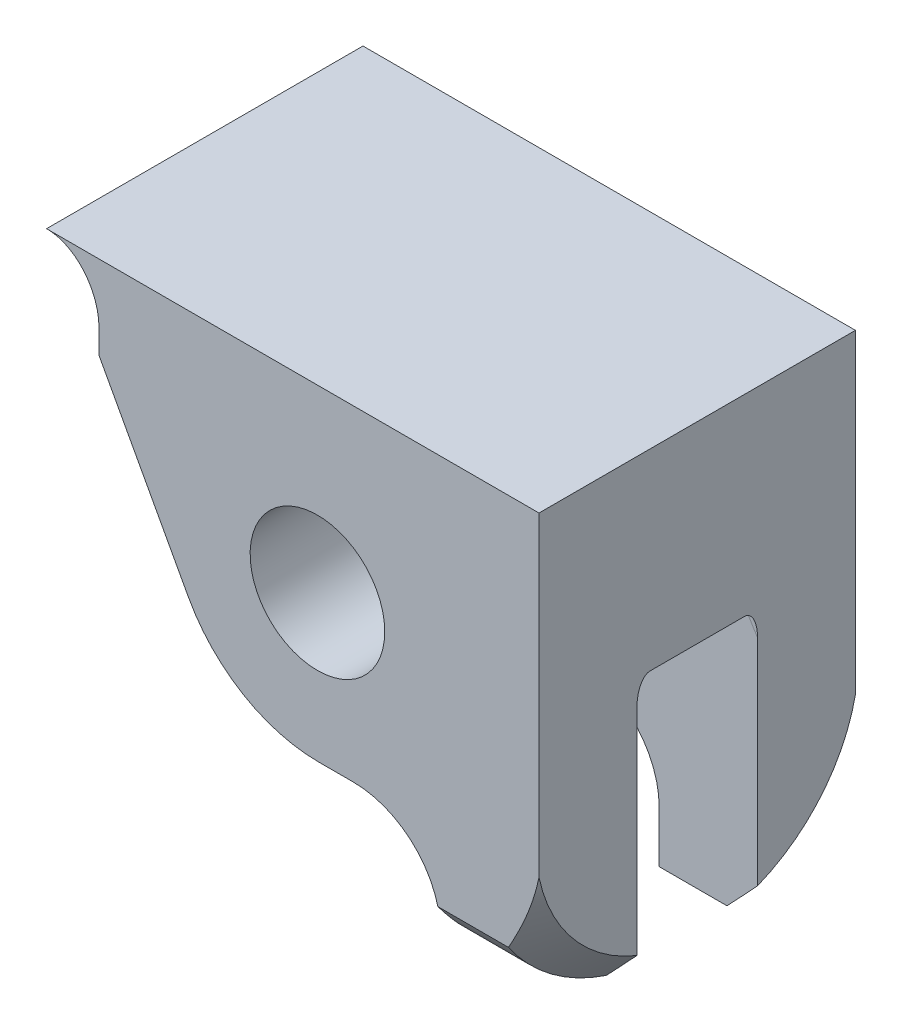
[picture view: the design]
ISO-10303-21;
HEADER;
FILE_DESCRIPTION(('STEP AP214'),'2;1');
FILE_NAME('part.step','',(''),(''),'','','');
FILE_SCHEMA(('AUTOMOTIVE_DESIGN { 1 0 10303 214 1 1 1 1 }'));
ENDSEC;
DATA;
#1=APPLICATION_CONTEXT('core data for automotive mechanical design processes');
#2=APPLICATION_PROTOCOL_DEFINITION('international standard','automotive_design',2000,#1);
#3=PRODUCT_CONTEXT('',#1,'mechanical');
#4=PRODUCT('Part','Part','',(#3));
#5=PRODUCT_RELATED_PRODUCT_CATEGORY('part','',(#4));
#6=PRODUCT_DEFINITION_FORMATION('','',#4);
#7=PRODUCT_DEFINITION_CONTEXT('part definition',#1,'design');
#8=PRODUCT_DEFINITION('design','',#6,#7);
#9=PRODUCT_DEFINITION_SHAPE('','',#8);
#10=(LENGTH_UNIT() NAMED_UNIT(*) SI_UNIT(.MILLI.,.METRE.));
#11=(NAMED_UNIT(*) PLANE_ANGLE_UNIT() SI_UNIT($,.RADIAN.));
#12=(NAMED_UNIT(*) SI_UNIT($,.STERADIAN.) SOLID_ANGLE_UNIT());
#13=UNCERTAINTY_MEASURE_WITH_UNIT(LENGTH_MEASURE(1.E-05),#10,'distance_accuracy_value','');
#14=(GEOMETRIC_REPRESENTATION_CONTEXT(3) GLOBAL_UNCERTAINTY_ASSIGNED_CONTEXT((#13)) GLOBAL_UNIT_ASSIGNED_CONTEXT((#10,
#11,#12)) REPRESENTATION_CONTEXT('',''));
#15=CARTESIAN_POINT('',(0.,0.,0.));
#16=DIRECTION('',(0.,0.,1.));
#17=DIRECTION('',(1.,0.,0.));
#18=AXIS2_PLACEMENT_3D('',#15,#16,#17);
#19=CARTESIAN_POINT('',(-20.8250166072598,0.,0.));
#20=DIRECTION('',(1.,0.,0.));
#21=DIRECTION('',(0.,0.,-1.));
#22=AXIS2_PLACEMENT_3D('',#19,#20,#21);
#23=PLANE('',#22);
#24=DIRECTION('',(0.,0.,-1.));
#25=VECTOR('',#24,1.);
#26=CARTESIAN_POINT('',(-20.8250166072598,-7.54952779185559,0.));
#27=LINE('',#26,#25);
#28=CARTESIAN_POINT('',(-20.8250166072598,-7.54952779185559,4.5974));
#29=VERTEX_POINT('',#28);
#30=CARTESIAN_POINT('',(-20.8250166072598,-7.54952779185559,-4.5974));
#31=VERTEX_POINT('',#30);
#32=EDGE_CURVE('E35',#29,#31,#27,.T.);
#33=ORIENTED_EDGE('',*,*,#32,.T.);
#34=CARTESIAN_POINT('',(-20.8250166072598,0.,0.));
#35=DIRECTION('',(-1.,0.,0.));
#36=DIRECTION('',(0.,0.,1.));
#37=AXIS2_PLACEMENT_3D('',#34,#35,#36);
#38=CIRCLE('',#37,8.83919999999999);
#39=EDGE_CURVE('E46',#31,#29,#38,.T.);
#40=ORIENTED_EDGE('',*,*,#39,.T.);
#41=EDGE_LOOP('',(#33,#40));
#42=FACE_BOUND('',#41,.T.);
#43=ADVANCED_FACE('F32',(#42),#23,.F.);
#44=CARTESIAN_POINT('',(0.,-7.54952779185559,0.));
#45=DIRECTION('',(0.,1.,0.));
#46=DIRECTION('',(0.,0.,1.));
#47=AXIS2_PLACEMENT_3D('',#44,#45,#46);
#48=PLANE('',#47);
#49=DIRECTION('',(1.,0.,0.));
#50=VECTOR('',#49,1.);
#51=CARTESIAN_POINT('',(-47.752,-7.54952779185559,4.5974));
#52=LINE('',#51,#50);
#53=CARTESIAN_POINT('',(-6.5151,-7.54952779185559,4.5974));
#54=VERTEX_POINT('',#53);
#55=EDGE_CURVE('E274',#29,#54,#52,.T.);
#56=ORIENTED_EDGE('',*,*,#55,.T.);
#57=DIRECTION('',(0.,0.,-1.));
#58=VECTOR('',#57,1.);
#59=CARTESIAN_POINT('',(-6.51509999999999,-7.54952779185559,0.));
#60=LINE('',#59,#58);
#61=CARTESIAN_POINT('',(-6.5151,-7.54952779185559,-4.59740000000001));
#62=VERTEX_POINT('',#61);
#63=EDGE_CURVE('E11',#54,#62,#60,.T.);
#64=ORIENTED_EDGE('',*,*,#63,.T.);
#65=DIRECTION('',(1.,0.,0.));
#66=VECTOR('',#65,1.);
#67=CARTESIAN_POINT('',(-47.752,-7.54952779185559,-4.5974));
#68=LINE('',#67,#66);
#69=EDGE_CURVE('E273',#31,#62,#68,.T.);
#70=ORIENTED_EDGE('',*,*,#69,.F.);
#71=ORIENTED_EDGE('',*,*,#32,.F.);
#72=EDGE_LOOP('',(#56,#64,#70,#71));
#73=FACE_BOUND('',#72,.T.);
#74=ADVANCED_FACE('F348',(#73),#48,.T.);
#75=CARTESIAN_POINT('',(-19.3010166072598,-10.3632,0.));
#76=DIRECTION('',(1.,0.,0.));
#77=DIRECTION('',(0.,0.,-1.));
#78=AXIS2_PLACEMENT_3D('',#75,#76,#77);
#79=PLANE('',#78);
#80=DIRECTION('',(0.,1.,0.));
#81=VECTOR('',#80,1.);
#82=CARTESIAN_POINT('',(-19.3010166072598,-7.54952779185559,4.5974));
#83=LINE('',#82,#81);
#84=CARTESIAN_POINT('',(-19.3010166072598,-9.9761533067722,4.5974));
#85=VERTEX_POINT('',#84);
#86=CARTESIAN_POINT('',(-19.3010166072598,-9.28761688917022,4.5974));
#87=VERTEX_POINT('',#86);
#88=EDGE_CURVE('E299',#85,#87,#83,.T.);
#89=ORIENTED_EDGE('',*,*,#88,.T.);
#90=CARTESIAN_POINT('',(-19.3010166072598,0.,0.));
#91=DIRECTION('',(-1.,0.,0.));
#92=DIRECTION('',(0.,0.,1.));
#93=AXIS2_PLACEMENT_3D('',#90,#91,#92);
#94=CIRCLE('',#93,10.3632);
#95=CARTESIAN_POINT('',(-19.3010166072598,-9.97615330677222,2.80575826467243));
#96=VERTEX_POINT('',#95);
#97=EDGE_CURVE('E507',#96,#87,#94,.T.);
#98=ORIENTED_EDGE('',*,*,#97,.F.);
#99=DIRECTION('',(0.,0.,-1.));
#100=VECTOR('',#99,1.);
#101=CARTESIAN_POINT('',(-19.3010166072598,-9.9761533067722,-5.14985));
#102=LINE('',#101,#100);
#103=EDGE_CURVE('E302',#85,#96,#102,.T.);
#104=ORIENTED_EDGE('',*,*,#103,.F.);
#105=EDGE_LOOP('',(#89,#98,#104));
#106=FACE_BOUND('',#105,.T.);
#107=ADVANCED_FACE('F351',(#106),#79,.F.);
#108=DIRECTION('',(0.,-1.,0.));
#109=VECTOR('',#108,1.);
#110=CARTESIAN_POINT('',(-19.3010166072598,-18.9244220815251,-4.5974));
#111=LINE('',#110,#109);
#112=CARTESIAN_POINT('',(-19.3010166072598,-9.28761688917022,-4.5974));
#113=VERTEX_POINT('',#112);
#114=CARTESIAN_POINT('',(-19.3010166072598,-9.9761533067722,-4.5974));
#115=VERTEX_POINT('',#114);
#116=EDGE_CURVE('E437',#113,#115,#111,.T.);
#117=ORIENTED_EDGE('',*,*,#116,.T.);
#118=CARTESIAN_POINT('',(-19.3010166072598,-9.97615330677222,-2.80575826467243));
#119=VERTEX_POINT('',#118);
#120=EDGE_CURVE('E296',#119,#115,#102,.T.);
#121=ORIENTED_EDGE('',*,*,#120,.F.);
#122=EDGE_CURVE('E509',#113,#119,#94,.T.);
#123=ORIENTED_EDGE('',*,*,#122,.F.);
#124=EDGE_LOOP('',(#117,#121,#123));
#125=FACE_BOUND('',#124,.T.);
#126=ADVANCED_FACE('F358',(#125),#79,.F.);
#127=CARTESIAN_POINT('',(-12.954,-12.7762,-5.14985));
#128=DIRECTION('',(0.,0.,1.));
#129=DIRECTION('',(1.,0.,0.));
#130=AXIS2_PLACEMENT_3D('',#127,#128,#129);
#131=CYLINDRICAL_SURFACE('',#130,1.9558);
#132=CARTESIAN_POINT('',(-12.954,-12.7762,-4.5974));
#133=DIRECTION('',(0.,0.,-1.));
#134=DIRECTION('',(0.,1.,0.));
#135=AXIS2_PLACEMENT_3D('',#132,#133,#134);
#136=CIRCLE('',#135,1.9558);
#137=CARTESIAN_POINT('',(-12.954,-10.8204,-4.5974));
#138=VERTEX_POINT('',#137);
#139=EDGE_CURVE('E222',#138,#138,#136,.T.);
#140=ORIENTED_EDGE('',*,*,#139,.T.);
#141=EDGE_LOOP('',(#140));
#142=FACE_BOUND('',#141,.T.);
#143=CARTESIAN_POINT('',(-12.954,-12.7762,-1.7526));
#144=DIRECTION('',(0.,0.,1.));
#145=DIRECTION('',(1.,0.,0.));
#146=AXIS2_PLACEMENT_3D('',#143,#144,#145);
#147=CIRCLE('',#146,1.9558);
#148=CARTESIAN_POINT('',(-10.9982,-12.7762,-1.7526));
#149=VERTEX_POINT('',#148);
#150=EDGE_CURVE('E501',#149,#149,#147,.F.);
#151=ORIENTED_EDGE('',*,*,#150,.F.);
#152=EDGE_LOOP('',(#151));
#153=FACE_BOUND('',#152,.T.);
#154=ADVANCED_FACE('F525',(#142,#153),#131,.F.);
#155=CARTESIAN_POINT('',(-9.3726,-19.558,-5.14985));
#156=DIRECTION('',(1.,0.,0.));
#157=DIRECTION('',(0.,1.,0.));
#158=AXIS2_PLACEMENT_3D('',#155,#156,#157);
#159=PLANE('',#158);
#160=DIRECTION('',(0.,-1.,0.));
#161=VECTOR('',#160,1.);
#162=CARTESIAN_POINT('',(-9.3726,-19.558,-1.7526));
#163=LINE('',#162,#161);
#164=CARTESIAN_POINT('',(-9.3726,-19.558,-1.7526));
#165=VERTEX_POINT('',#164);
#166=CARTESIAN_POINT('',(-9.3726,-21.0540472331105,-1.7526));
#167=VERTEX_POINT('',#166);
#168=EDGE_CURVE('E493',#165,#167,#163,.T.);
#169=ORIENTED_EDGE('',*,*,#168,.F.);
#170=DIRECTION('',(0.,0.,1.));
#171=VECTOR('',#170,1.);
#172=CARTESIAN_POINT('',(-9.3726,-19.558,-5.14985));
#173=LINE('',#172,#171);
#174=CARTESIAN_POINT('',(-9.3726,-19.558,-4.08774314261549));
#175=VERTEX_POINT('',#174);
#176=EDGE_CURVE('E226',#175,#165,#173,.T.);
#177=ORIENTED_EDGE('',*,*,#176,.F.);
#178=CARTESIAN_POINT('',(-9.37260000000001,-15.748,0.));
#179=DIRECTION('',(1.,0.,0.));
#180=DIRECTION('',(0.,1.,0.));
#181=AXIS2_PLACEMENT_3D('',#178,#179,#180);
#182=CIRCLE('',#181,5.588);
#183=EDGE_CURVE('E293',#175,#167,#182,.F.);
#184=ORIENTED_EDGE('',*,*,#183,.T.);
#185=EDGE_LOOP('',(#169,#177,#184));
#186=FACE_BOUND('',#185,.T.);
#187=ADVANCED_FACE('F561',(#186),#159,.F.);
#188=CARTESIAN_POINT('',(-11.9126,-19.558,-5.14985));
#189=DIRECTION('',(0.,0.,1.));
#190=DIRECTION('',(1.,0.,0.));
#191=AXIS2_PLACEMENT_3D('',#188,#189,#190);
#192=CYLINDRICAL_SURFACE('',#191,2.54);
#193=CARTESIAN_POINT('',(-11.9126,-19.558,-1.7526));
#194=DIRECTION('',(0.,0.,1.));
#195=DIRECTION('',(1.,0.,0.));
#196=AXIS2_PLACEMENT_3D('',#193,#194,#195);
#197=CIRCLE('',#196,2.54);
#198=CARTESIAN_POINT('',(-11.9126,-17.018,-1.7526));
#199=VERTEX_POINT('',#198);
#200=EDGE_CURVE('E491',#199,#165,#197,.F.);
#201=ORIENTED_EDGE('',*,*,#200,.F.);
#202=DIRECTION('',(0.,0.,1.));
#203=VECTOR('',#202,1.);
#204=CARTESIAN_POINT('',(-11.9126,-17.018,-5.14985));
#205=LINE('',#204,#203);
#206=CARTESIAN_POINT('',(-11.9126,-17.018,-4.5974));
#207=VERTEX_POINT('',#206);
#208=EDGE_CURVE('E442',#207,#199,#205,.T.);
#209=ORIENTED_EDGE('',*,*,#208,.F.);
#210=CARTESIAN_POINT('',(-11.9126,-19.558,-4.5974));
#211=DIRECTION('',(0.,0.,-1.));
#212=DIRECTION('',(0.,1.,0.));
#213=AXIS2_PLACEMENT_3D('',#210,#211,#212);
#214=CIRCLE('',#213,2.54);
#215=CARTESIAN_POINT('',(-9.4528888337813,-18.9244220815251,-4.5974));
#216=VERTEX_POINT('',#215);
#217=EDGE_CURVE('E290',#207,#216,#214,.T.);
#218=ORIENTED_EDGE('',*,*,#217,.T.);
#219=CARTESIAN_POINT('',(-9.97381391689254,-17.9170525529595,-5.14985));
#220=CARTESIAN_POINT('',(-9.92846202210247,-17.9706111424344,-5.12730256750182));
#221=CARTESIAN_POINT('',(-9.88570291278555,-18.0256568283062,-5.10312410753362));
#222=CARTESIAN_POINT('',(-9.80549953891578,-18.1379772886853,-5.05148902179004));
#223=CARTESIAN_POINT('',(-9.76805189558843,-18.1952506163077,-5.02403450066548));
#224=CARTESIAN_POINT('',(-9.6987847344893,-18.3109469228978,-4.9660053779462));
#225=CARTESIAN_POINT('',(-9.66692780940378,-18.3693591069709,-4.93545385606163));
#226=CARTESIAN_POINT('',(-9.60848600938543,-18.4870290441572,-4.8711365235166));
#227=CARTESIAN_POINT('',(-9.5819015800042,-18.546286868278,-4.83737044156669));
#228=CARTESIAN_POINT('',(-9.50999982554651,-18.724094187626,-4.73154460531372));
#229=CARTESIAN_POINT('',(-9.47233207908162,-18.8430243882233,-4.65478617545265));
#230=CARTESIAN_POINT('',(-9.4155283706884,-19.0775349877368,-4.49004914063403));
#231=CARTESIAN_POINT('',(-9.3964151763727,-19.1931111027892,-4.40205690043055));
#232=CARTESIAN_POINT('',(-9.38087414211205,-19.3485949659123,-4.27371216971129));
#233=CARTESIAN_POINT('',(-9.37772427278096,-19.3912949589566,-4.2373694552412));
#234=CARTESIAN_POINT('',(-9.37359111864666,-19.4755163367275,-4.1634707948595));
#235=CARTESIAN_POINT('',(-9.37260143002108,-19.5170408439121,-4.1259187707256));
#236=CARTESIAN_POINT('',(-9.3726,-19.558,-4.08774314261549));
#237=B_SPLINE_CURVE_WITH_KNOTS('',3,(#219,#220,#221,#222,#223,#224,#225,#226,#227,#228,#229,
#230,#231,#232,#233,#234,#235,#236),.UNSPECIFIED.,.F.,.F.,(4,2,2,2,2,2,2,2,4),(0.,
0.221040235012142,0.441939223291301,0.661298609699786,0.880676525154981,1.31813990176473,
1.75613939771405,1.92457157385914,2.0925037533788),.UNSPECIFIED.);
#238=EDGE_CURVE('E230',#216,#175,#237,.T.);
#239=ORIENTED_EDGE('',*,*,#238,.T.);
#240=ORIENTED_EDGE('',*,*,#176,.T.);
#241=EDGE_LOOP('',(#201,#209,#218,#239,#240));
#242=FACE_BOUND('',#241,.T.);
#243=ADVANCED_FACE('F253',(#242),#192,.F.);
#244=CARTESIAN_POINT('',(-12.9086657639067,-17.018,-5.14985));
#245=DIRECTION('',(0.,1.,0.));
#246=DIRECTION('',(-1.,0.,0.));
#247=AXIS2_PLACEMENT_3D('',#244,#245,#246);
#248=PLANE('',#247);
#249=DIRECTION('',(1.,0.,0.));
#250=VECTOR('',#249,1.);
#251=CARTESIAN_POINT('',(-12.9086657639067,-17.018,-1.7526));
#252=LINE('',#251,#250);
#253=CARTESIAN_POINT('',(-12.9086657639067,-17.018,-1.7526));
#254=VERTEX_POINT('',#253);
#255=EDGE_CURVE('E489',#254,#199,#252,.T.);
#256=ORIENTED_EDGE('',*,*,#255,.F.);
#257=DIRECTION('',(0.,0.,1.));
#258=VECTOR('',#257,1.);
#259=CARTESIAN_POINT('',(-12.9086657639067,-17.018,-5.14985));
#260=LINE('',#259,#258);
#261=CARTESIAN_POINT('',(-12.9086657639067,-17.018,-4.5974));
#262=VERTEX_POINT('',#261);
#263=EDGE_CURVE('E231',#262,#254,#260,.T.);
#264=ORIENTED_EDGE('',*,*,#263,.F.);
#265=DIRECTION('',(1.,0.,0.));
#266=VECTOR('',#265,1.);
#267=CARTESIAN_POINT('',(-47.752,-17.0180000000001,-4.5974));
#268=LINE('',#267,#266);
#269=EDGE_CURVE('E288',#262,#207,#268,.T.);
#270=ORIENTED_EDGE('',*,*,#269,.T.);
#271=ORIENTED_EDGE('',*,*,#208,.T.);
#272=EDGE_LOOP('',(#256,#264,#270,#271));
#273=FACE_BOUND('',#272,.T.);
#274=ADVANCED_FACE('F531',(#273),#248,.F.);
#275=CARTESIAN_POINT('',(-12.9086657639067,-12.7,-5.14985));
#276=DIRECTION('',(0.,0.,1.));
#277=DIRECTION('',(1.,0.,0.));
#278=AXIS2_PLACEMENT_3D('',#275,#276,#277);
#279=CYLINDRICAL_SURFACE('',#278,4.318);
#280=CARTESIAN_POINT('',(-12.9086657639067,-12.7,-1.7526));
#281=DIRECTION('',(0.,0.,1.));
#282=DIRECTION('',(1.,0.,0.));
#283=AXIS2_PLACEMENT_3D('',#280,#281,#282);
#284=CIRCLE('',#283,4.318);
#285=CARTESIAN_POINT('',(-16.7033980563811,-14.760371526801,-1.7526));
#286=VERTEX_POINT('',#285);
#287=EDGE_CURVE('E487',#286,#254,#284,.T.);
#288=ORIENTED_EDGE('',*,*,#287,.F.);
#289=DIRECTION('',(0.,0.,1.));
#290=VECTOR('',#289,1.);
#291=CARTESIAN_POINT('',(-16.7033980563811,-14.760371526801,-5.14985));
#292=LINE('',#291,#290);
#293=CARTESIAN_POINT('',(-16.7033980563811,-14.760371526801,-4.5974));
#294=VERTEX_POINT('',#293);
#295=EDGE_CURVE('E216',#294,#286,#292,.T.);
#296=ORIENTED_EDGE('',*,*,#295,.F.);
#297=CARTESIAN_POINT('',(-12.9086657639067,-12.7,-4.5974));
#298=DIRECTION('',(0.,0.,-1.));
#299=DIRECTION('',(0.,1.,0.));
#300=AXIS2_PLACEMENT_3D('',#297,#298,#299);
#301=CIRCLE('',#300,4.318);
#302=EDGE_CURVE('E286',#294,#262,#301,.F.);
#303=ORIENTED_EDGE('',*,*,#302,.T.);
#304=ORIENTED_EDGE('',*,*,#263,.T.);
#305=EDGE_LOOP('',(#288,#296,#303,#304));
#306=FACE_BOUND('',#305,.T.);
#307=ADVANCED_FACE('F523',(#306),#279,.T.);
#308=CARTESIAN_POINT('',(-19.9183318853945,-8.8392,-5.14985));
#309=DIRECTION('',(0.878817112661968,0.477158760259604,0.));
#310=DIRECTION('',(-0.477158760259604,0.878817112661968,0.));
#311=AXIS2_PLACEMENT_3D('',#308,#309,#310);
#312=PLANE('',#311);
#313=DIRECTION('',(0.477158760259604,-0.878817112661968,0.));
#314=VECTOR('',#313,1.);
#315=CARTESIAN_POINT('',(-19.9183318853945,-8.8392,-1.7526));
#316=LINE('',#315,#314);
#317=CARTESIAN_POINT('',(-19.3273360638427,-9.92767889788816,-1.7526));
#318=VERTEX_POINT('',#317);
#319=EDGE_CURVE('E485',#318,#286,#316,.T.);
#320=ORIENTED_EDGE('',*,*,#319,.F.);
#321=CARTESIAN_POINT('',(-19.4856993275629,-9.63601004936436,0.));
#322=CARTESIAN_POINT('',(-19.4845018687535,-9.63821549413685,-0.00913515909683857));
#323=CARTESIAN_POINT('',(-19.4833098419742,-9.64041093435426,-0.0182737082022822));
#324=CARTESIAN_POINT('',(-19.4177100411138,-9.76123073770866,-0.523680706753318));
#325=CARTESIAN_POINT('',(-19.3693390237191,-9.85031906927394,-1.02984150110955));
#326=CARTESIAN_POINT('',(-19.3084355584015,-9.96248929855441,-2.05247010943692));
#327=CARTESIAN_POINT('',(-19.2959541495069,-9.98547719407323,-2.56895155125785));
#328=CARTESIAN_POINT('',(-19.3063645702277,-9.9663035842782,-3.34237693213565));
#329=CARTESIAN_POINT('',(-19.3147285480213,-9.95089905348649,-3.60039859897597));
#330=CARTESIAN_POINT('',(-19.3415154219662,-9.90156376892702,-4.11416173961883));
#331=CARTESIAN_POINT('',(-19.3599368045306,-9.86763580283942,-4.36990355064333));
#332=CARTESIAN_POINT('',(-19.4071596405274,-9.78066215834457,-4.87789800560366));
#333=CARTESIAN_POINT('',(-19.4359894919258,-9.72756417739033,-5.13013912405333));
#334=CARTESIAN_POINT('',(-19.5042264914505,-9.60188725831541,-5.62844766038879));
#335=CARTESIAN_POINT('',(-19.5436415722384,-9.52929371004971,-5.87451029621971));
#336=CARTESIAN_POINT('',(-19.5884304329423,-9.44680289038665,-6.11630962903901));
#337=B_SPLINE_CURVE_WITH_KNOTS('',3,(#321,#322,#323,#324,#325,#326,#327,#328,#329,#330,#331,
#332,#333,#334,#335,#336),.UNSPECIFIED.,.F.,.F.,(4,2,2,2,2,2,2,4),(0.,0.0284215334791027,
1.57127409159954,3.11631967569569,3.89143286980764,4.66642944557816,5.44355666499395,
6.22126790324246),.UNSPECIFIED.);
#338=EDGE_CURVE('E429',#318,#119,#337,.T.);
#339=ORIENTED_EDGE('',*,*,#338,.T.);
#340=ORIENTED_EDGE('',*,*,#120,.T.);
#341=DIRECTION('',(0.477158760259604,-0.878817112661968,0.));
#342=VECTOR('',#341,1.);
#343=CARTESIAN_POINT('',(-22.0264254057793,-4.95657472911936,-4.59740000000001));
#344=LINE('',#343,#342);
#345=EDGE_CURVE('E284',#115,#294,#344,.T.);
#346=ORIENTED_EDGE('',*,*,#345,.T.);
#347=ORIENTED_EDGE('',*,*,#295,.T.);
#348=EDGE_LOOP('',(#320,#339,#340,#346,#347));
#349=FACE_BOUND('',#348,.T.);
#350=ADVANCED_FACE('F517',(#349),#312,.F.);
#351=CARTESIAN_POINT('',(-12.954,-12.7762,1.7526));
#352=DIRECTION('',(0.,0.,1.));
#353=DIRECTION('',(1.,0.,0.));
#354=AXIS2_PLACEMENT_3D('',#351,#352,#353);
#355=CIRCLE('',#354,1.9558);
#356=CARTESIAN_POINT('',(-10.9982,-12.7762,1.7526));
#357=VERTEX_POINT('',#356);
#358=EDGE_CURVE('E482',#357,#357,#355,.F.);
#359=ORIENTED_EDGE('',*,*,#358,.T.);
#360=EDGE_LOOP('',(#359));
#361=FACE_BOUND('',#360,.T.);
#362=CARTESIAN_POINT('',(-12.954,-12.7762,4.5974));
#363=DIRECTION('',(0.,0.,1.));
#364=DIRECTION('',(0.,-1.,0.));
#365=AXIS2_PLACEMENT_3D('',#362,#363,#364);
#366=CIRCLE('',#365,1.9558);
#367=CARTESIAN_POINT('',(-12.954,-14.732,4.5974));
#368=VERTEX_POINT('',#367);
#369=EDGE_CURVE('E217',#368,#368,#366,.T.);
#370=ORIENTED_EDGE('',*,*,#369,.T.);
#371=EDGE_LOOP('',(#370));
#372=FACE_BOUND('',#371,.T.);
#373=ADVANCED_FACE('F516',(#361,#372),#131,.F.);
#374=CARTESIAN_POINT('',(-19.4856993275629,-9.63601004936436,0.));
#375=CARTESIAN_POINT('',(-19.4845018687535,-9.63821549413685,0.00913515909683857));
#376=CARTESIAN_POINT('',(-19.4833098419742,-9.64041093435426,0.0182737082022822));
#377=CARTESIAN_POINT('',(-19.4177100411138,-9.76123073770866,0.523680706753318));
#378=CARTESIAN_POINT('',(-19.3693390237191,-9.85031906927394,1.02984150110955));
#379=CARTESIAN_POINT('',(-19.3084355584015,-9.96248929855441,2.05247010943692));
#380=CARTESIAN_POINT('',(-19.2959541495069,-9.98547719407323,2.56895155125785));
#381=CARTESIAN_POINT('',(-19.3063645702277,-9.9663035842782,3.34237693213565));
#382=CARTESIAN_POINT('',(-19.3147285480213,-9.95089905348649,3.60039859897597));
#383=CARTESIAN_POINT('',(-19.3415154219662,-9.90156376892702,4.11416173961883));
#384=CARTESIAN_POINT('',(-19.3599368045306,-9.86763580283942,4.36990355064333));
#385=CARTESIAN_POINT('',(-19.4071596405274,-9.78066215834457,4.87789800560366));
#386=CARTESIAN_POINT('',(-19.4359894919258,-9.72756417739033,5.13013912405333));
#387=CARTESIAN_POINT('',(-19.5042264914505,-9.60188725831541,5.62844766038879));
#388=CARTESIAN_POINT('',(-19.5436415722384,-9.52929371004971,5.87451029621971));
#389=CARTESIAN_POINT('',(-19.5884304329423,-9.44680289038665,6.11630962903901));
#390=B_SPLINE_CURVE_WITH_KNOTS('',3,(#374,#375,#376,#377,#378,#379,#380,#381,#382,#383,#384,
#385,#386,#387,#388,#389),.UNSPECIFIED.,.F.,.F.,(4,2,2,2,2,2,2,4),(0.,0.0284215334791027,
1.57127409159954,3.11631967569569,3.89143286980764,4.66642944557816,5.44355666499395,
6.22126790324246),.UNSPECIFIED.);
#391=CARTESIAN_POINT('',(-19.3273360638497,-9.92767889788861,1.7526));
#392=VERTEX_POINT('',#391);
#393=EDGE_CURVE('E210',#96,#392,#390,.F.);
#394=ORIENTED_EDGE('',*,*,#393,.T.);
#395=DIRECTION('',(0.477158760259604,-0.878817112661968,0.));
#396=VECTOR('',#395,1.);
#397=CARTESIAN_POINT('',(-19.9183318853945,-8.8392,1.7526));
#398=LINE('',#397,#396);
#399=CARTESIAN_POINT('',(-16.7033980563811,-14.760371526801,1.7526));
#400=VERTEX_POINT('',#399);
#401=EDGE_CURVE('E196',#392,#400,#398,.T.);
#402=ORIENTED_EDGE('',*,*,#401,.T.);
#403=CARTESIAN_POINT('',(-16.7033980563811,-14.760371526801,4.5974));
#404=VERTEX_POINT('',#403);
#405=EDGE_CURVE('E207',#400,#404,#292,.T.);
#406=ORIENTED_EDGE('',*,*,#405,.T.);
#407=DIRECTION('',(-0.477158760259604,0.878817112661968,0.));
#408=VECTOR('',#407,1.);
#409=CARTESIAN_POINT('',(-26.7963199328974,3.82847814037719,4.5974));
#410=LINE('',#409,#408);
#411=EDGE_CURVE('E228',#404,#85,#410,.T.);
#412=ORIENTED_EDGE('',*,*,#411,.T.);
#413=ORIENTED_EDGE('',*,*,#103,.T.);
#414=EDGE_LOOP('',(#394,#402,#406,#412,#413));
#415=FACE_BOUND('',#414,.T.);
#416=ADVANCED_FACE('F205',(#415),#312,.F.);
#417=ORIENTED_EDGE('',*,*,#405,.F.);
#418=CARTESIAN_POINT('',(-12.9086657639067,-12.7,1.7526));
#419=DIRECTION('',(0.,0.,1.));
#420=DIRECTION('',(1.,0.,0.));
#421=AXIS2_PLACEMENT_3D('',#418,#419,#420);
#422=CIRCLE('',#421,4.318);
#423=CARTESIAN_POINT('',(-12.9086657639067,-17.018,1.7526));
#424=VERTEX_POINT('',#423);
#425=EDGE_CURVE('E190',#400,#424,#422,.T.);
#426=ORIENTED_EDGE('',*,*,#425,.T.);
#427=CARTESIAN_POINT('',(-12.9086657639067,-17.018,4.5974));
#428=VERTEX_POINT('',#427);
#429=EDGE_CURVE('E441',#424,#428,#260,.T.);
#430=ORIENTED_EDGE('',*,*,#429,.T.);
#431=CARTESIAN_POINT('',(-12.9086657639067,-12.7,4.5974));
#432=DIRECTION('',(0.,0.,1.));
#433=DIRECTION('',(0.,-1.,0.));
#434=AXIS2_PLACEMENT_3D('',#431,#432,#433);
#435=CIRCLE('',#434,4.318);
#436=EDGE_CURVE('E214',#428,#404,#435,.F.);
#437=ORIENTED_EDGE('',*,*,#436,.T.);
#438=EDGE_LOOP('',(#417,#426,#430,#437));
#439=FACE_BOUND('',#438,.T.);
#440=ADVANCED_FACE('F212',(#439),#279,.T.);
#441=ORIENTED_EDGE('',*,*,#429,.F.);
#442=DIRECTION('',(1.,0.,0.));
#443=VECTOR('',#442,1.);
#444=CARTESIAN_POINT('',(-12.9086657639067,-17.018,1.7526));
#445=LINE('',#444,#443);
#446=CARTESIAN_POINT('',(-11.9126,-17.018,1.7526));
#447=VERTEX_POINT('',#446);
#448=EDGE_CURVE('E199',#424,#447,#445,.T.);
#449=ORIENTED_EDGE('',*,*,#448,.T.);
#450=CARTESIAN_POINT('',(-11.9126,-17.018,4.5974));
#451=VERTEX_POINT('',#450);
#452=EDGE_CURVE('E444',#447,#451,#205,.T.);
#453=ORIENTED_EDGE('',*,*,#452,.T.);
#454=DIRECTION('',(-1.,0.,0.));
#455=VECTOR('',#454,1.);
#456=CARTESIAN_POINT('',(-47.752,-17.0180000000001,4.5974));
#457=LINE('',#456,#455);
#458=EDGE_CURVE('E262',#451,#428,#457,.T.);
#459=ORIENTED_EDGE('',*,*,#458,.T.);
#460=EDGE_LOOP('',(#441,#449,#453,#459));
#461=FACE_BOUND('',#460,.T.);
#462=ADVANCED_FACE('F251',(#461),#248,.F.);
#463=ORIENTED_EDGE('',*,*,#452,.F.);
#464=CARTESIAN_POINT('',(-11.9126,-19.558,1.7526));
#465=DIRECTION('',(0.,0.,1.));
#466=DIRECTION('',(1.,0.,0.));
#467=AXIS2_PLACEMENT_3D('',#464,#465,#466);
#468=CIRCLE('',#467,2.54);
#469=CARTESIAN_POINT('',(-9.3726,-19.558,1.7526));
#470=VERTEX_POINT('',#469);
#471=EDGE_CURVE('E460',#447,#470,#468,.F.);
#472=ORIENTED_EDGE('',*,*,#471,.T.);
#473=CARTESIAN_POINT('',(-9.3726,-19.558,4.08774314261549));
#474=VERTEX_POINT('',#473);
#475=EDGE_CURVE('E220',#470,#474,#173,.T.);
#476=ORIENTED_EDGE('',*,*,#475,.T.);
#477=CARTESIAN_POINT('',(-9.3726,-19.558,4.08774314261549));
#478=CARTESIAN_POINT('',(-9.37259911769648,-19.4958343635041,4.1457020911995));
#479=CARTESIAN_POINT('',(-9.37488359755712,-19.432305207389,4.20224681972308));
#480=CARTESIAN_POINT('',(-9.38460987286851,-19.3028833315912,4.3122775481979));
#481=CARTESIAN_POINT('',(-9.39205896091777,-19.2369873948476,4.36575910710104));
#482=CARTESIAN_POINT('',(-9.41277054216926,-19.1029454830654,4.46959934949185));
#483=CARTESIAN_POINT('',(-9.42607001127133,-19.0347877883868,4.51993580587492));
#484=CARTESIAN_POINT('',(-9.45899893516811,-18.8973603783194,4.61674700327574));
#485=CARTESIAN_POINT('',(-9.47862446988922,-18.8280913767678,4.66322411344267));
#486=CARTESIAN_POINT('',(-9.5404322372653,-18.6417564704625,4.78236613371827));
#487=CARTESIAN_POINT('',(-9.58887601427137,-18.5242428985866,4.85132839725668));
#488=CARTESIAN_POINT('',(-9.67673331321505,-18.3510630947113,4.94511389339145));
#489=CARTESIAN_POINT('',(-9.70847832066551,-18.2939544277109,4.97472015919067));
#490=CARTESIAN_POINT('',(-9.7770511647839,-18.1812767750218,5.03078995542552));
#491=CARTESIAN_POINT('',(-9.81387592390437,-18.1257068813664,5.05725537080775));
#492=CARTESIAN_POINT('',(-9.8721448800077,-18.0449917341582,5.09415450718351));
#493=CARTESIAN_POINT('',(-9.89167725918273,-18.0189948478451,5.10579234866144));
#494=CARTESIAN_POINT('',(-9.93188940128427,-17.967575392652,5.12835416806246));
#495=CARTESIAN_POINT('',(-9.95256940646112,-17.9421529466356,5.13927799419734));
#496=CARTESIAN_POINT('',(-9.97381391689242,-17.9170525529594,5.14985000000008));
#497=B_SPLINE_CURVE_WITH_KNOTS('',3,(#477,#478,#479,#480,#481,#482,#483,#484,#485,#486,#487,
#488,#489,#490,#491,#492,#493,#494,#495,#496),.UNSPECIFIED.,.F.,.F.,(4,2,2,2,2,2,2,2,2,4),(0.,
0.254973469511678,0.510307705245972,0.767279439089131,1.02409224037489,1.45567178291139,
1.67066730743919,1.88553314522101,1.98911752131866,2.09272384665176),.UNSPECIFIED.);
#498=CARTESIAN_POINT('',(-9.4528888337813,-18.9244220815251,4.5974));
#499=VERTEX_POINT('',#498);
#500=EDGE_CURVE('E257',#474,#499,#497,.T.);
#501=ORIENTED_EDGE('',*,*,#500,.T.);
#502=CARTESIAN_POINT('',(-11.9126,-19.558,4.5974));
#503=DIRECTION('',(0.,0.,1.));
#504=DIRECTION('',(0.,-1.,0.));
#505=AXIS2_PLACEMENT_3D('',#502,#503,#504);
#506=CIRCLE('',#505,2.54);
#507=EDGE_CURVE('E239',#499,#451,#506,.T.);
#508=ORIENTED_EDGE('',*,*,#507,.T.);
#509=EDGE_LOOP('',(#463,#472,#476,#501,#508));
#510=FACE_BOUND('',#509,.T.);
#511=ADVANCED_FACE('F245',(#510),#192,.F.);
#512=ORIENTED_EDGE('',*,*,#475,.F.);
#513=DIRECTION('',(0.,-1.,0.));
#514=VECTOR('',#513,1.);
#515=CARTESIAN_POINT('',(-9.3726,-19.558,1.7526));
#516=LINE('',#515,#514);
#517=CARTESIAN_POINT('',(-9.3726,-21.0540472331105,1.7526));
#518=VERTEX_POINT('',#517);
#519=EDGE_CURVE('E474',#470,#518,#516,.T.);
#520=ORIENTED_EDGE('',*,*,#519,.T.);
#521=EDGE_CURVE('E292',#518,#474,#182,.F.);
#522=ORIENTED_EDGE('',*,*,#521,.T.);
#523=EDGE_LOOP('',(#512,#520,#522));
#524=FACE_BOUND('',#523,.T.);
#525=ADVANCED_FACE('F250',(#524),#159,.F.);
#526=CARTESIAN_POINT('',(-47.752,-15.748,0.));
#527=DIRECTION('',(1.,0.,0.));
#528=DIRECTION('',(0.,0.,-1.));
#529=AXIS2_PLACEMENT_3D('',#526,#527,#528);
#530=CYLINDRICAL_SURFACE('',#529,5.588);
#531=DIRECTION('',(1.,0.,0.));
#532=VECTOR('',#531,1.);
#533=CARTESIAN_POINT('',(-47.752,-18.9244220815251,-4.5974));
#534=LINE('',#533,#532);
#535=CARTESIAN_POINT('',(-7.40409999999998,-18.9244220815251,-4.5974));
#536=VERTEX_POINT('',#535);
#537=EDGE_CURVE('E268',#216,#536,#534,.T.);
#538=ORIENTED_EDGE('',*,*,#537,.T.);
#539=CARTESIAN_POINT('',(-7.40409999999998,-15.748,0.));
#540=DIRECTION('',(1.,0.,0.));
#541=DIRECTION('',(0.,0.,-1.));
#542=AXIS2_PLACEMENT_3D('',#539,#540,#541);
#543=CIRCLE('',#542,5.588);
#544=CARTESIAN_POINT('',(-7.40409999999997,-21.0540472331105,-1.7526));
#545=VERTEX_POINT('',#544);
#546=EDGE_CURVE('E400',#536,#545,#543,.F.);
#547=ORIENTED_EDGE('',*,*,#546,.T.);
#548=DIRECTION('',(1.,0.,0.));
#549=VECTOR('',#548,1.);
#550=CARTESIAN_POINT('',(-47.752,-21.0540472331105,-1.7526));
#551=LINE('',#550,#549);
#552=EDGE_CURVE('E496',#545,#167,#551,.F.);
#553=ORIENTED_EDGE('',*,*,#552,.T.);
#554=ORIENTED_EDGE('',*,*,#183,.F.);
#555=ORIENTED_EDGE('',*,*,#238,.F.);
#556=EDGE_LOOP('',(#538,#547,#553,#554,#555));
#557=FACE_BOUND('',#556,.T.);
#558=ADVANCED_FACE('F557',(#557),#530,.T.);
#559=CARTESIAN_POINT('',(-15.8260487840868,-19.2269271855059,-1.7526));
#560=DIRECTION('',(0.,0.,1.));
#561=DIRECTION('',(1.,0.,0.));
#562=AXIS2_PLACEMENT_3D('',#559,#560,#561);
#563=PLANE('',#562);
#564=ORIENTED_EDGE('',*,*,#552,.F.);
#565=CARTESIAN_POINT('',(-7.40409999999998,-21.0540472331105,-1.7526));
#566=CARTESIAN_POINT('',(-7.32960475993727,-20.9755920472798,-1.7526));
#567=CARTESIAN_POINT('',(-7.25519352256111,-20.8970569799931,-1.7526));
#568=CARTESIAN_POINT('',(-7.10656692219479,-20.7398029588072,-1.7526));
#569=CARTESIAN_POINT('',(-7.03235155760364,-20.661084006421,-1.7526));
#570=CARTESIAN_POINT('',(-6.88414320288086,-20.5034366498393,-1.7526));
#571=CARTESIAN_POINT('',(-6.81015021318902,-20.4245082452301,-1.7526));
#572=CARTESIAN_POINT('',(-6.66242233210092,-20.2664090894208,-1.7526));
#573=CARTESIAN_POINT('',(-6.58868744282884,-20.1872383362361,-1.7526));
#574=CARTESIAN_POINT('',(-6.51509999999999,-20.1079305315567,-1.7526));
#575=B_SPLINE_CURVE_WITH_KNOTS('',3,(#565,#566,#567,#568,#569,#570,#571,#572,#573,#574),
.UNSPECIFIED.,.F.,.F.,(4,2,2,2,4),(0.,0.324565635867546,0.649128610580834,0.973692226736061,
1.29825850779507),.UNSPECIFIED.);
#576=CARTESIAN_POINT('',(-6.51509999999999,-20.1079305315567,-1.7526));
#577=VERTEX_POINT('',#576);
#578=EDGE_CURVE('E403',#545,#577,#575,.T.);
#579=ORIENTED_EDGE('',*,*,#578,.T.);
#580=DIRECTION('',(0.,-1.,0.));
#581=VECTOR('',#580,1.);
#582=CARTESIAN_POINT('',(-6.51509999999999,-6.2484,-1.7526));
#583=LINE('',#582,#581);
#584=CARTESIAN_POINT('',(-6.51509999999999,-13.8655778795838,-1.7526));
#585=VERTEX_POINT('',#584);
#586=EDGE_CURVE('E498',#585,#577,#583,.T.);
#587=ORIENTED_EDGE('',*,*,#586,.F.);
#588=CARTESIAN_POINT('',(-15.8260487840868,-19.2269271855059,-1.7526));
#589=DIRECTION('',(0.,0.,1.));
#590=DIRECTION('',(1.,0.,0.));
#591=AXIS2_PLACEMENT_3D('',#588,#589,#590);
#592=CIRCLE('',#591,10.7442);
#593=CARTESIAN_POINT('',(-19.676215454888,-9.19627166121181,-1.7526));
#594=VERTEX_POINT('',#593);
#595=EDGE_CURVE('E588',#585,#594,#592,.T.);
#596=ORIENTED_EDGE('',*,*,#595,.T.);
#597=CARTESIAN_POINT('',(-19.3150833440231,-10.4234714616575,-1.7526));
#598=CARTESIAN_POINT('',(-19.3267510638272,-10.5099207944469,-1.7526));
#599=CARTESIAN_POINT('',(-19.3456700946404,-10.59545276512,-1.7526));
#600=CARTESIAN_POINT('',(-19.3975725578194,-10.7622144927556,-1.7526));
#601=CARTESIAN_POINT('',(-19.430571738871,-10.8434393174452,-1.7526));
#602=CARTESIAN_POINT('',(-19.5097812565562,-10.9991847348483,-1.7526));
#603=CARTESIAN_POINT('',(-19.5559916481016,-11.073705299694,-1.7526));
#604=CARTESIAN_POINT('',(-19.6603625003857,-11.2138214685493,-1.7526));
#605=CARTESIAN_POINT('',(-19.7185197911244,-11.2794194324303,-1.7526));
#606=CARTESIAN_POINT('',(-19.844620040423,-11.3992249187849,-1.7526));
#607=CARTESIAN_POINT('',(-19.9124742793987,-11.4535257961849,-1.7526));
#608=CARTESIAN_POINT('',(-20.0564271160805,-11.5498085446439,-1.7526));
#609=CARTESIAN_POINT('',(-20.1325255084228,-11.5917907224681,-1.7526));
#610=CARTESIAN_POINT('',(-20.2898572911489,-11.6617441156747,-1.7526));
#611=CARTESIAN_POINT('',(-20.3710213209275,-11.6898713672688,-1.7526));
#612=CARTESIAN_POINT('',(-20.5369384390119,-11.7319821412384,-1.7526));
#613=CARTESIAN_POINT('',(-20.6216913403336,-11.7459663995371,-1.7526));
#614=CARTESIAN_POINT('',(-20.7916877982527,-11.7593150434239,-1.7526));
#615=CARTESIAN_POINT('',(-20.8769226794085,-11.758790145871,-1.7526));
#616=CARTESIAN_POINT('',(-21.0460879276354,-11.7434101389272,-1.7526));
#617=CARTESIAN_POINT('',(-21.1300183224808,-11.7285553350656,-1.7526));
#618=CARTESIAN_POINT('',(-21.2940485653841,-11.6850000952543,-1.7526));
#619=CARTESIAN_POINT('',(-21.3741547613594,-11.65632354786,-1.7526));
#620=CARTESIAN_POINT('',(-21.5284463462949,-11.5859875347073,-1.7526));
#621=CARTESIAN_POINT('',(-21.6026316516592,-11.5443278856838,-1.7526));
#622=CARTESIAN_POINT('',(-21.7433532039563,-11.4490310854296,-1.7526));
#623=CARTESIAN_POINT('',(-21.8098531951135,-11.395340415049,-1.7526));
#624=CARTESIAN_POINT('',(-21.9330015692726,-11.2776536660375,-1.7526));
#625=CARTESIAN_POINT('',(-21.9896495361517,-11.2136571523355,-1.7526));
#626=CARTESIAN_POINT('',(-22.0920815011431,-11.0765266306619,-1.7526));
#627=CARTESIAN_POINT('',(-22.1377555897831,-11.0033105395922,-1.7526));
#628=CARTESIAN_POINT('',(-22.2163323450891,-10.8503205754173,-1.7526));
#629=CARTESIAN_POINT('',(-22.2492342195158,-10.7705462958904,-1.7526));
#630=CARTESIAN_POINT('',(-22.3017495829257,-10.6056771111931,-1.7526));
#631=CARTESIAN_POINT('',(-22.3211981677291,-10.5205296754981,-1.7526));
#632=CARTESIAN_POINT('',(-22.345685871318,-10.3481871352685,-1.7526));
#633=CARTESIAN_POINT('',(-22.3507240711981,-10.2609919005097,-1.7526));
#634=CARTESIAN_POINT('',(-22.3462690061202,-10.0860676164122,-1.7526));
#635=CARTESIAN_POINT('',(-22.3366247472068,-9.9983423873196,-1.7526));
#636=CARTESIAN_POINT('',(-22.3028052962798,-9.82573625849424,-1.7526));
#637=CARTESIAN_POINT('',(-22.2786295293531,-9.74085547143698,-1.7526));
#638=CARTESIAN_POINT('',(-22.2162810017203,-9.57603272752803,-1.7526));
#639=CARTESIAN_POINT('',(-22.1780563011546,-9.49611040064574,-1.7526));
#640=CARTESIAN_POINT('',(-22.0886474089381,-9.34387181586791,-1.7526));
#641=CARTESIAN_POINT('',(-22.0374634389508,-9.27155542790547,-1.7526));
#642=CARTESIAN_POINT('',(-21.9239035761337,-9.13713540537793,-1.7526));
#643=CARTESIAN_POINT('',(-21.8616038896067,-9.07496743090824,-1.7526));
#644=CARTESIAN_POINT('',(-21.7273028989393,-8.96217864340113,-1.7526));
#645=CARTESIAN_POINT('',(-21.655302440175,-8.91155682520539,-1.7526));
#646=CARTESIAN_POINT('',(-21.504866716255,-8.82418439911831,-1.7526));
#647=CARTESIAN_POINT('',(-21.4265529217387,-8.78722469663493,-1.7526));
#648=CARTESIAN_POINT('',(-21.2647570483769,-8.72724829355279,-1.7526));
#649=CARTESIAN_POINT('',(-21.1812755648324,-8.70422999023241,-1.7526));
#650=CARTESIAN_POINT('',(-21.0130961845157,-8.67317714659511,-1.7526));
#651=CARTESIAN_POINT('',(-20.9284456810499,-8.66488559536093,-1.7526));
#652=CARTESIAN_POINT('',(-20.75896639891,-8.66276581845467,-1.7526));
#653=CARTESIAN_POINT('',(-20.6741376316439,-8.66893669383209,-1.7526));
#654=CARTESIAN_POINT('',(-20.5074553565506,-8.69542461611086,-1.7526));
#655=CARTESIAN_POINT('',(-20.4255828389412,-8.71562237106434,-1.7526));
#656=CARTESIAN_POINT('',(-20.2663581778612,-8.7693930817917,-1.7526));
#657=CARTESIAN_POINT('',(-20.1890061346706,-8.80296633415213,-1.7526));
#658=CARTESIAN_POINT('',(-20.0404658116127,-8.88270184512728,-1.7526));
#659=CARTESIAN_POINT('',(-19.9693193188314,-8.92894188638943,-1.7526));
#660=CARTESIAN_POINT('',(-19.8356369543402,-9.03252513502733,-1.7526));
#661=CARTESIAN_POINT('',(-19.7731014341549,-9.08986879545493,-1.7526));
#662=CARTESIAN_POINT('',(-19.6573040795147,-9.21503446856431,-1.7526));
#663=CARTESIAN_POINT('',(-19.6042122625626,-9.28301374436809,-1.7526));
#664=CARTESIAN_POINT('',(-19.5099544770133,-9.42681595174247,-1.7526));
#665=CARTESIAN_POINT('',(-19.468792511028,-9.50264150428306,-1.7526));
#666=CARTESIAN_POINT('',(-19.3988597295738,-9.66138327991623,-1.7526));
#667=CARTESIAN_POINT('',(-19.3703173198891,-9.74440003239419,-1.7526));
#668=CARTESIAN_POINT('',(-19.3274692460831,-9.9139596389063,-1.7526));
#669=CARTESIAN_POINT('',(-19.3131477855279,-10.0004984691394,-1.7526));
#670=CARTESIAN_POINT('',(-19.3015911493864,-10.1435120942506,-1.7526));
#671=CARTESIAN_POINT('',(-19.3000782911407,-10.1996759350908,-1.7526));
#672=CARTESIAN_POINT('',(-19.3030706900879,-10.31184360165,-1.7526));
#673=CARTESIAN_POINT('',(-19.3075759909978,-10.3678474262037,-1.7526));
#674=CARTESIAN_POINT('',(-19.3150833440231,-10.4234714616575,-1.7526));
#675=B_SPLINE_CURVE_WITH_KNOTS('',3,(#597,#598,#599,#600,#601,#602,#603,#604,#605,#606,#607,
#608,#609,#610,#611,#612,#613,#614,#615,#616,#617,#618,#619,#620,#621,#622,#623,#624,#625,#626,
#627,#628,#629,#630,#631,#632,#633,#634,#635,#636,#637,#638,#639,#640,#641,#642,#643,#644,#645,
#646,#647,#648,#649,#650,#651,#652,#653,#654,#655,#656,#657,#658,#659,#660,#661,#662,#663,#664,
#665,#666,#667,#668,#669,#670,#671,#672,#673,#674),.UNSPECIFIED.,.T.,.F.,(4,2,2,2,2,2,2,2,2,2,2,
2,2,2,2,2,2,2,2,2,2,2,2,2,2,2,2,2,2,2,2,2,2,2,2,2,2,2,4),(0.,0.26149736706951,0.523287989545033,
0.785079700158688,1.0468020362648,1.30626721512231,1.56572593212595,1.82219167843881,
2.07864407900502,2.33314007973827,2.58763065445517,2.84168295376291,3.09573883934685,
3.35094813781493,3.60616821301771,3.86384682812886,4.12154142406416,4.38234127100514,
4.64315774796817,4.90667463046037,5.17020193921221,5.43471349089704,5.69922051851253,
5.96197934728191,6.22471529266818,6.48324500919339,6.74174499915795,6.99568760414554,
7.24961442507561,7.50140774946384,7.75320665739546,8.00658785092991,8.25997938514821,
8.5175513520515,8.77520963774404,9.03735746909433,9.29921378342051,9.46746763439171,
9.63572270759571),.UNSPECIFIED.);
#676=EDGE_CURVE('E540',#594,#318,#675,.T.);
#677=ORIENTED_EDGE('',*,*,#676,.T.);
#678=ORIENTED_EDGE('',*,*,#319,.T.);
#679=ORIENTED_EDGE('',*,*,#287,.T.);
#680=ORIENTED_EDGE('',*,*,#255,.T.);
#681=ORIENTED_EDGE('',*,*,#200,.T.);
#682=ORIENTED_EDGE('',*,*,#168,.T.);
#683=EDGE_LOOP('',(#564,#579,#587,#596,#677,#678,#679,#680,#681,#682));
#684=FACE_BOUND('',#683,.T.);
#685=ORIENTED_EDGE('',*,*,#150,.T.);
#686=EDGE_LOOP('',(#685));
#687=FACE_BOUND('',#686,.T.);
#688=ADVANCED_FACE('F323',(#684,#687),#563,.T.);
#689=CARTESIAN_POINT('',(-47.752,-18.9244220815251,-4.5974));
#690=DIRECTION('',(0.,0.,-1.));
#691=DIRECTION('',(0.,1.,0.));
#692=AXIS2_PLACEMENT_3D('',#689,#690,#691);
#693=PLANE('',#692);
#694=DIRECTION('',(0.,-1.,0.));
#695=VECTOR('',#694,1.);
#696=CARTESIAN_POINT('',(-6.5151,-18.9244220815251,-4.5974));
#697=LINE('',#696,#695);
#698=CARTESIAN_POINT('',(-6.5151,-16.7198612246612,-4.5974));
#699=VERTEX_POINT('',#698);
#700=EDGE_CURVE('E272',#62,#699,#697,.T.);
#701=ORIENTED_EDGE('',*,*,#700,.T.);
#702=CARTESIAN_POINT('',(-6.51509999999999,-16.7198612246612,-4.59740000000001));
#703=CARTESIAN_POINT('',(-6.55557764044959,-16.9156542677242,-4.5974));
#704=CARTESIAN_POINT('',(-6.60724781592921,-17.1086960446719,-4.5974));
#705=CARTESIAN_POINT('',(-6.7284500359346,-17.4878724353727,-4.5974));
#706=CARTESIAN_POINT('',(-6.79787264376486,-17.6740416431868,-4.5974));
#707=CARTESIAN_POINT('',(-6.95051233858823,-18.0401157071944,-4.5974));
#708=CARTESIAN_POINT('',(-7.03370537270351,-18.2200308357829,-4.5974));
#709=CARTESIAN_POINT('',(-7.16671735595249,-18.4864244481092,-4.5974));
#710=CARTESIAN_POINT('',(-7.21258023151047,-18.5749114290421,-4.5974));
#711=CARTESIAN_POINT('',(-7.30665568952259,-18.750600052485,-4.5974));
#712=CARTESIAN_POINT('',(-7.35486767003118,-18.8378020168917,-4.5974));
#713=CARTESIAN_POINT('',(-7.40409999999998,-18.9244220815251,-4.5974));
#714=B_SPLINE_CURVE_WITH_KNOTS('',3,(#702,#703,#704,#705,#706,#707,#708,#709,#710,#711,#712,
#713),.UNSPECIFIED.,.F.,.F.,(4,2,2,2,2,4),(0.,0.598852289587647,1.19409833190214,
1.78831541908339,2.08728415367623,2.38617667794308),.UNSPECIFIED.);
#715=EDGE_CURVE('E412',#699,#536,#714,.T.);
#716=ORIENTED_EDGE('',*,*,#715,.T.);
#717=ORIENTED_EDGE('',*,*,#537,.F.);
#718=ORIENTED_EDGE('',*,*,#217,.F.);
#719=ORIENTED_EDGE('',*,*,#269,.F.);
#720=ORIENTED_EDGE('',*,*,#302,.F.);
#721=ORIENTED_EDGE('',*,*,#345,.F.);
#722=ORIENTED_EDGE('',*,*,#116,.F.);
#723=CARTESIAN_POINT('',(-19.485584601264,-10.0923721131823,-4.59740000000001));
#724=CARTESIAN_POINT('',(-19.5255573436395,-10.1732972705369,-4.59740000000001));
#725=CARTESIAN_POINT('',(-19.5719452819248,-10.2510986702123,-4.59740000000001));
#726=CARTESIAN_POINT('',(-19.6769208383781,-10.3980724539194,-4.59740000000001));
#727=CARTESIAN_POINT('',(-19.735514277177,-10.4672406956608,-4.5974));
#728=CARTESIAN_POINT('',(-19.8639685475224,-10.5947088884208,-4.5974));
#729=CARTESIAN_POINT('',(-19.9338661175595,-10.6529720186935,-4.5974));
#730=CARTESIAN_POINT('',(-20.0830123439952,-10.7559716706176,-4.5974));
#731=CARTESIAN_POINT('',(-20.1622570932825,-10.8007138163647,-4.5974));
#732=CARTESIAN_POINT('',(-20.3224765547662,-10.872348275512,-4.5974));
#733=CARTESIAN_POINT('',(-20.4030280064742,-10.9001872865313,-4.5974));
#734=CARTESIAN_POINT('',(-20.5678021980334,-10.9410475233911,-4.5974));
#735=CARTESIAN_POINT('',(-20.6520236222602,-10.9540740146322,-4.5974));
#736=CARTESIAN_POINT('',(-20.8167085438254,-10.9644417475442,-4.5974));
#737=CARTESIAN_POINT('',(-20.8971207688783,-10.9626144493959,-4.5974));
#738=CARTESIAN_POINT('',(-21.0564544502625,-10.945318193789,-4.5974));
#739=CARTESIAN_POINT('',(-21.1353760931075,-10.9298509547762,-4.5974));
#740=CARTESIAN_POINT('',(-21.2886526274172,-10.8861325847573,-4.5974));
#741=CARTESIAN_POINT('',(-21.3630476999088,-10.858021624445,-4.5974));
#742=CARTESIAN_POINT('',(-21.5062771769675,-10.7901021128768,-4.5974));
#743=CARTESIAN_POINT('',(-21.5751110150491,-10.7502923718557,-4.5974));
#744=CARTESIAN_POINT('',(-21.7078331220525,-10.6588211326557,-4.5974));
#745=CARTESIAN_POINT('',(-21.7714771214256,-10.6068059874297,-4.5974));
#746=CARTESIAN_POINT('',(-21.8898139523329,-10.4934507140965,-4.5974));
#747=CARTESIAN_POINT('',(-21.9445044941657,-10.4321082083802,-4.59740000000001));
#748=CARTESIAN_POINT('',(-22.0474042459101,-10.2974574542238,-4.59740000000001));
#749=CARTESIAN_POINT('',(-22.0949186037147,-10.2236188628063,-4.59740000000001));
#750=CARTESIAN_POINT('',(-22.1780134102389,-10.0695201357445,-4.59740000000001));
#751=CARTESIAN_POINT('',(-22.2135896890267,-9.98925776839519,-4.59740000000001));
#752=CARTESIAN_POINT('',(-22.275037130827,-9.817220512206,-4.59740000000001));
#753=CARTESIAN_POINT('',(-22.299801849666,-9.7250504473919,-4.59740000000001));
#754=CARTESIAN_POINT('',(-22.3347967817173,-9.53799527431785,-4.59740000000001));
#755=CARTESIAN_POINT('',(-22.3450213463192,-9.44310912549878,-4.59740000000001));
#756=CARTESIAN_POINT('',(-22.3513359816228,-9.24508927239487,-4.59740000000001));
#757=CARTESIAN_POINT('',(-22.3462021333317,-9.14191550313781,-4.59740000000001));
#758=CARTESIAN_POINT('',(-22.3194685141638,-8.9377032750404,-4.59740000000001));
#759=CARTESIAN_POINT('',(-22.2978627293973,-8.83666560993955,-4.59740000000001));
#760=CARTESIAN_POINT('',(-22.2373461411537,-8.63507357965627,-4.59740000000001));
#761=CARTESIAN_POINT('',(-22.1977237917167,-8.53473122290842,-4.59740000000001));
#762=CARTESIAN_POINT('',(-22.1016376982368,-8.34238275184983,-4.59740000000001));
#763=CARTESIAN_POINT('',(-22.0451712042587,-8.25037800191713,-4.59740000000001));
#764=CARTESIAN_POINT('',(-21.9184441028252,-8.0811870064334,-4.59740000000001));
#765=CARTESIAN_POINT('',(-21.8487171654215,-8.00360358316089,-4.59740000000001));
#766=CARTESIAN_POINT('',(-21.6956246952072,-7.86326511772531,-4.59740000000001));
#767=CARTESIAN_POINT('',(-21.6122735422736,-7.80049460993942,-4.59740000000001));
#768=CARTESIAN_POINT('',(-21.4451824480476,-7.70034087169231,-4.59740000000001));
#769=CARTESIAN_POINT('',(-21.3627488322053,-7.66078585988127,-4.59740000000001));
#770=CARTESIAN_POINT('',(-21.1917025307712,-7.5987638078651,-4.59740000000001));
#771=CARTESIAN_POINT('',(-21.103098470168,-7.57627341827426,-4.59740000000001));
#772=CARTESIAN_POINT('',(-20.9360780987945,-7.55194726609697,-4.59740000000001));
#773=CARTESIAN_POINT('',(-20.8580186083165,-7.54761610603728,-4.59740000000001));
#774=CARTESIAN_POINT('',(-20.7023945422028,-7.55298240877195,-4.59740000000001));
#775=CARTESIAN_POINT('',(-20.6248298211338,-7.56267553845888,-4.59740000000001));
#776=CARTESIAN_POINT('',(-20.4769196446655,-7.59455873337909,-4.59740000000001));
#777=CARTESIAN_POINT('',(-20.4064134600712,-7.61601576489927,-4.59740000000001));
#778=CARTESIAN_POINT('',(-20.2697026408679,-7.66981018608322,-4.59740000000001));
#779=CARTESIAN_POINT('',(-20.2034987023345,-7.70214933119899,-4.59740000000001));
#780=CARTESIAN_POINT('',(-20.0729254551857,-7.77855500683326,-4.59740000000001));
#781=CARTESIAN_POINT('',(-20.0088984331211,-7.82320381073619,-4.59740000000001));
#782=CARTESIAN_POINT('',(-19.888173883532,-7.92148103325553,-4.59740000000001));
#783=CARTESIAN_POINT('',(-19.8314796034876,-7.97511340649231,-4.59740000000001));
#784=CARTESIAN_POINT('',(-19.7194317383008,-8.09700351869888,-4.59740000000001));
#785=CARTESIAN_POINT('',(-19.665158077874,-8.16625333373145,-4.59740000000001));
#786=CARTESIAN_POINT('',(-19.5674219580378,-8.31199052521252,-4.59740000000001));
#787=CARTESIAN_POINT('',(-19.5239647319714,-8.38848138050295,-4.59740000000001));
#788=CARTESIAN_POINT('',(-19.4433889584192,-8.5571140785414,-4.59740000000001));
#789=CARTESIAN_POINT('',(-19.4078220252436,-8.64999948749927,-4.59740000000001));
#790=CARTESIAN_POINT('',(-19.3515234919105,-8.84020136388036,-4.59740000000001));
#791=CARTESIAN_POINT('',(-19.3308022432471,-8.93752087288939,-4.59740000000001));
#792=CARTESIAN_POINT('',(-19.3036375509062,-9.14170489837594,-4.59740000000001));
#793=CARTESIAN_POINT('',(-19.2984012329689,-9.2487320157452,-4.59740000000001));
#794=CARTESIAN_POINT('',(-19.3060580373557,-9.46207267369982,-4.59740000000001));
#795=CARTESIAN_POINT('',(-19.3189311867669,-9.56838687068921,-4.59740000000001));
#796=CARTESIAN_POINT('',(-19.3562368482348,-9.74532380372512,-4.59740000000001));
#797=CARTESIAN_POINT('',(-19.3759620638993,-9.81696628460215,-4.59740000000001));
#798=CARTESIAN_POINT('',(-19.4242092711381,-9.95723302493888,-4.59740000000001));
#799=CARTESIAN_POINT('',(-19.4527300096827,-10.02585771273,-4.59740000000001));
#800=CARTESIAN_POINT('',(-19.485584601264,-10.0923721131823,-4.59740000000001));
#801=B_SPLINE_CURVE_WITH_KNOTS('',3,(#723,#724,#725,#726,#727,#728,#729,#730,#731,#732,#733,
#734,#735,#736,#737,#738,#739,#740,#741,#742,#743,#744,#745,#746,#747,#748,#749,#750,#751,#752,
#753,#754,#755,#756,#757,#758,#759,#760,#761,#762,#763,#764,#765,#766,#767,#768,#769,#770,#771,
#772,#773,#774,#775,#776,#777,#778,#779,#780,#781,#782,#783,#784,#785,#786,#787,#788,#789,#790,
#791,#792,#793,#794,#795,#796,#797,#798,#799,#800),.UNSPECIFIED.,.T.,.F.,(4,2,2,2,2,2,2,2,2,2,2,
2,2,2,2,2,2,2,2,2,2,2,2,2,2,2,2,2,2,2,2,2,2,2,2,2,2,2,4),(0.,0.270537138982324,
0.541203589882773,0.812768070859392,1.08421943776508,1.33857515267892,1.59284042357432,
1.83297515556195,2.07307963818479,2.31058549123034,2.54811550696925,2.79363615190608,
3.03921948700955,3.30152422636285,3.56392049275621,3.84902662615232,4.13424348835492,
4.44277850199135,4.75142621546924,5.07349332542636,5.39561304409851,5.70679174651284,
6.01764410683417,6.29029906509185,6.56258027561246,6.79589287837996,7.0291334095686,
7.24926426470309,7.46943064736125,7.70266851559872,7.93600932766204,8.19891370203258,
8.46194503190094,8.75906831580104,9.05639857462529,9.37636562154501,9.6959800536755,
9.91837292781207,10.1407341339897),.UNSPECIFIED.);
#802=EDGE_CURVE('E423',#31,#113,#801,.T.);
#803=ORIENTED_EDGE('',*,*,#802,.F.);
#804=ORIENTED_EDGE('',*,*,#69,.T.);
#805=EDGE_LOOP('',(#701,#716,#717,#718,#719,#720,#721,#722,#803,#804));
#806=FACE_BOUND('',#805,.T.);
#807=ORIENTED_EDGE('',*,*,#139,.F.);
#808=EDGE_LOOP('',(#807));
#809=FACE_BOUND('',#808,.T.);
#810=ADVANCED_FACE('F417',(#806,#809),#693,.T.);
#811=CARTESIAN_POINT('',(-7.40409999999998,-15.748,0.));
#812=DIRECTION('',(-1.,0.,0.));
#813=DIRECTION('',(0.,0.,1.));
#814=AXIS2_PLACEMENT_3D('',#811,#812,#813);
#815=CONICAL_SURFACE('',#814,5.588,0.785398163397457);
#816=ORIENTED_EDGE('',*,*,#715,.F.);
#817=CARTESIAN_POINT('',(-6.51509999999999,-15.748,0.));
#818=DIRECTION('',(1.,0.,0.));
#819=DIRECTION('',(0.,0.,-1.));
#820=AXIS2_PLACEMENT_3D('',#817,#818,#819);
#821=CIRCLE('',#820,4.699);
#822=EDGE_CURVE('E410',#577,#699,#821,.T.);
#823=ORIENTED_EDGE('',*,*,#822,.F.);
#824=ORIENTED_EDGE('',*,*,#578,.F.);
#825=ORIENTED_EDGE('',*,*,#546,.F.);
#826=EDGE_LOOP('',(#816,#823,#824,#825));
#827=FACE_BOUND('',#826,.T.);
#828=ADVANCED_FACE('F345',(#827),#815,.T.);
#829=CARTESIAN_POINT('',(-15.8260487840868,-19.2269271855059,-1.7526));
#830=DIRECTION('',(0.,0.,1.));
#831=DIRECTION('',(1.,0.,0.));
#832=AXIS2_PLACEMENT_3D('',#829,#830,#831);
#833=CYLINDRICAL_SURFACE('',#832,11.1252);
#834=CARTESIAN_POINT('',(-19.9968684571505,-8.91313359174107,-1.75280000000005));
#835=CARTESIAN_POINT('',(-20.0206021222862,-8.92273013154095,-1.62449681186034));
#836=CARTESIAN_POINT('',(-20.0425945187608,-8.93172051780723,-1.49578634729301));
#837=CARTESIAN_POINT('',(-20.0822060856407,-8.94803354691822,-1.23749784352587));
#838=CARTESIAN_POINT('',(-20.0998220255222,-8.95535495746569,-1.10791923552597));
#839=CARTESIAN_POINT('',(-20.1297368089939,-8.96785260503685,-0.848165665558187));
#840=CARTESIAN_POINT('',(-20.1420411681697,-8.97303106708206,-0.717991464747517));
#841=CARTESIAN_POINT('',(-20.160679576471,-8.98089601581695,-0.45717015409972));
#842=CARTESIAN_POINT('',(-20.1670153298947,-8.98358321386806,-0.326523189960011));
#843=CARTESIAN_POINT('',(-20.1732917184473,-8.98624527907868,-0.0672626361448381));
#844=CARTESIAN_POINT('',(-20.1733390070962,-8.98626538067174,0.0613478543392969));
#845=CARTESIAN_POINT('',(-20.1673033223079,-8.98370532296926,0.318410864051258));
#846=CARTESIAN_POINT('',(-20.1612196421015,-8.98112486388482,0.446863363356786));
#847=CARTESIAN_POINT('',(-20.1432756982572,-8.973551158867,0.703210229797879));
#848=CARTESIAN_POINT('',(-20.131418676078,-8.96855926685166,0.831104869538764));
#849=CARTESIAN_POINT('',(-20.1025670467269,-8.95649835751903,1.086194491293));
#850=CARTESIAN_POINT('',(-20.0855729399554,-8.94942954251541,1.21338954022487));
#851=CARTESIAN_POINT('',(-20.0612233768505,-8.93939089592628,1.37464851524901));
#852=CARTESIAN_POINT('',(-20.0558619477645,-8.93718515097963,1.40907398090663));
#853=CARTESIAN_POINT('',(-20.044840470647,-8.93266144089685,1.47786478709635));
#854=CARTESIAN_POINT('',(-20.0391804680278,-8.93034349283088,1.51223013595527));
#855=CARTESIAN_POINT('',(-20.0275649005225,-8.92559830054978,1.58099186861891));
#856=CARTESIAN_POINT('',(-20.0216086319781,-8.92317079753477,1.61538811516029));
#857=CARTESIAN_POINT('',(-20.0094318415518,-8.91822093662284,1.68413154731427));
#858=CARTESIAN_POINT('',(-20.0032112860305,-8.9156985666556,1.71847872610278));
#859=CARTESIAN_POINT('',(-19.9968684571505,-8.91313359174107,1.75280000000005));
#860=B_SPLINE_CURVE_WITH_KNOTS('',3,(#834,#835,#836,#837,#838,#839,#840,#841,#842,#843,#844,
#845,#846,#847,#848,#849,#850,#851,#852,#853,#854,#855,#856,#857,#858,#859),.UNSPECIFIED.,.F.,
.F.,(4,2,2,2,2,2,2,2,2,2,2,2,4),(0.,0.392542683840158,0.785374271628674,1.17779695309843,
1.57010754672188,1.95576361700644,2.34146415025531,2.72694838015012,3.11239507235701,
3.21712534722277,3.32183973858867,3.42681596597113,3.53180559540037),.UNSPECIFIED.);
#861=CARTESIAN_POINT('',(-20.0616386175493,-8.93956339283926,-1.3716));
#862=VERTEX_POINT('',#861);
#863=CARTESIAN_POINT('',(-20.0616386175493,-8.93956339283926,1.3716));
#864=VERTEX_POINT('',#863);
#865=EDGE_CURVE('E309',#862,#864,#860,.T.);
#866=ORIENTED_EDGE('',*,*,#865,.F.);
#867=CARTESIAN_POINT('',(-15.8260487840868,-19.2269271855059,-1.3716));
#868=DIRECTION('',(0.,0.,1.));
#869=DIRECTION('',(1.,0.,0.));
#870=AXIS2_PLACEMENT_3D('',#867,#868,#869);
#871=CIRCLE('',#870,11.1252);
#872=CARTESIAN_POINT('',(-6.51509999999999,-13.1378954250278,-1.3716));
#873=VERTEX_POINT('',#872);
#874=EDGE_CURVE('E583',#862,#873,#871,.F.);
#875=ORIENTED_EDGE('',*,*,#874,.T.);
#876=DIRECTION('',(0.,0.,1.));
#877=VECTOR('',#876,1.);
#878=CARTESIAN_POINT('',(-6.51509999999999,-13.1378954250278,-1.7526));
#879=LINE('',#878,#877);
#880=CARTESIAN_POINT('',(-6.51509999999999,-13.1378954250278,1.3716));
#881=VERTEX_POINT('',#880);
#882=EDGE_CURVE('E504',#873,#881,#879,.T.);
#883=ORIENTED_EDGE('',*,*,#882,.T.);
#884=CARTESIAN_POINT('',(-15.8260487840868,-19.2269271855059,1.3716));
#885=DIRECTION('',(0.,0.,1.));
#886=DIRECTION('',(1.,0.,0.));
#887=AXIS2_PLACEMENT_3D('',#884,#885,#886);
#888=CIRCLE('',#887,11.1252);
#889=EDGE_CURVE('E584',#881,#864,#888,.T.);
#890=ORIENTED_EDGE('',*,*,#889,.T.);
#891=EDGE_LOOP('',(#866,#875,#883,#890));
#892=FACE_BOUND('',#891,.T.);
#893=ADVANCED_FACE('F325',(#892),#833,.F.);
#894=CARTESIAN_POINT('',(-20.8250166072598,0.,0.));
#895=DIRECTION('',(-1.,0.,0.));
#896=DIRECTION('',(0.,0.,1.));
#897=AXIS2_PLACEMENT_3D('',#894,#895,#896);
#898=TOROIDAL_SURFACE('',#897,10.3632,1.524);
#899=ORIENTED_EDGE('',*,*,#676,.F.);
#900=CARTESIAN_POINT('',(-19.676215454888,-9.19627166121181,-1.7526));
#901=CARTESIAN_POINT('',(-19.6920800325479,-9.17770582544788,-1.7526083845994));
#902=CARTESIAN_POINT('',(-19.7085791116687,-9.15976074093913,-1.75051751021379));
#903=CARTESIAN_POINT('',(-19.7422529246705,-9.12557872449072,-1.74255419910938));
#904=CARTESIAN_POINT('',(-19.7594238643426,-9.10933369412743,-1.73670073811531));
#905=CARTESIAN_POINT('',(-19.7939719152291,-9.07886482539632,-1.72164093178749));
#906=CARTESIAN_POINT('',(-19.8113483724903,-9.06463582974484,-1.71244336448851));
#907=CARTESIAN_POINT('',(-19.8458925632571,-9.03828928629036,-1.69103737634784));
#908=CARTESIAN_POINT('',(-19.8630598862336,-9.02617541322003,-1.6788238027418));
#909=CARTESIAN_POINT('',(-19.8983245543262,-9.00308740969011,-1.65032896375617));
#910=CARTESIAN_POINT('',(-19.9163454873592,-8.99234516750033,-1.63376455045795));
#911=CARTESIAN_POINT('',(-19.9507452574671,-8.9736402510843,-1.59761128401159));
#912=CARTESIAN_POINT('',(-19.9671242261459,-8.96567735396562,-1.57802267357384));
#913=CARTESIAN_POINT('',(-19.9943851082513,-8.95390424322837,-1.54008060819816));
#914=CARTESIAN_POINT('',(-20.0057191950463,-8.94959100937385,-1.52220783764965));
#915=CARTESIAN_POINT('',(-20.026006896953,-8.94297894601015,-1.48485663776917));
#916=CARTESIAN_POINT('',(-20.0349688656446,-8.94067298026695,-1.46538416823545));
#917=CARTESIAN_POINT('',(-20.0467695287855,-8.9386920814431,-1.43338256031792));
#918=CARTESIAN_POINT('',(-20.050614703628,-8.93832756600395,-1.4212617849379));
#919=CARTESIAN_POINT('',(-20.0570856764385,-8.93836322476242,-1.39666145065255));
#920=CARTESIAN_POINT('',(-20.0597076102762,-8.93876580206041,-1.38418088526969));
#921=CARTESIAN_POINT('',(-20.0616386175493,-8.93956339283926,-1.3716));
#922=B_SPLINE_CURVE_WITH_KNOTS('',3,(#900,#901,#902,#903,#904,#905,#906,#907,#908,#909,#910,
#911,#912,#913,#914,#915,#916,#917,#918,#919,#920,#921),.UNSPECIFIED.,.F.,.F.,(4,2,2,2,2,2,2,2,
2,2,4),(0.,0.0730719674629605,0.14577827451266,0.218295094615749,0.290936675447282,
0.370776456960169,0.450609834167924,0.515169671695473,0.579499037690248,0.617583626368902,
0.655787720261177),.UNSPECIFIED.);
#923=EDGE_CURVE('E375',#594,#862,#922,.T.);
#924=ORIENTED_EDGE('',*,*,#923,.T.);
#925=ORIENTED_EDGE('',*,*,#865,.T.);
#926=CARTESIAN_POINT('',(-20.0616386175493,-8.93956339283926,1.3716));
#927=CARTESIAN_POINT('',(-20.0585232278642,-8.93826725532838,1.39199656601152));
#928=CARTESIAN_POINT('',(-20.0535795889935,-8.9380149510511,1.41208103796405));
#929=CARTESIAN_POINT('',(-20.0407525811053,-8.93948160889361,1.45104101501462));
#930=CARTESIAN_POINT('',(-20.0328941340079,-8.94118410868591,1.46992522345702));
#931=CARTESIAN_POINT('',(-20.0149276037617,-8.94641223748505,1.50615874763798));
#932=CARTESIAN_POINT('',(-20.00483164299,-8.94992817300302,1.52351565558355));
#933=CARTESIAN_POINT('',(-19.9829226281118,-8.95868707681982,1.55668304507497));
#934=CARTESIAN_POINT('',(-19.9711054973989,-8.96393418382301,1.57248970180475));
#935=CARTESIAN_POINT('',(-19.9441250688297,-8.97712266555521,1.60495003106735));
#936=CARTESIAN_POINT('',(-19.9287345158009,-8.98537053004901,1.62129035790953));
#937=CARTESIAN_POINT('',(-19.8968807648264,-9.00406907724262,1.65148113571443));
#938=CARTESIAN_POINT('',(-19.8804169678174,-9.01452099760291,1.66533017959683));
#939=CARTESIAN_POINT('',(-19.8445497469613,-9.03920509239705,1.6920919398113));
#940=CARTESIAN_POINT('',(-19.8250606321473,-9.05376319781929,1.70459311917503));
#941=CARTESIAN_POINT('',(-19.786082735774,-9.08549344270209,1.72558933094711));
#942=CARTESIAN_POINT('',(-19.7665940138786,-9.10266094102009,1.73409136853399));
#943=CARTESIAN_POINT('',(-19.7351836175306,-9.13268005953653,1.74432766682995));
#944=CARTESIAN_POINT('',(-19.7230548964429,-9.14487126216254,1.74739557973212));
#945=CARTESIAN_POINT('',(-19.6992491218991,-9.17003053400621,1.75153368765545));
#946=CARTESIAN_POINT('',(-19.6875725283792,-9.18299936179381,1.75260189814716));
#947=CARTESIAN_POINT('',(-19.676215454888,-9.19627166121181,1.7526));
#948=B_SPLINE_CURVE_WITH_KNOTS('',3,(#926,#927,#928,#929,#930,#931,#932,#933,#934,#935,#936,
#937,#938,#939,#940,#941,#942,#943,#944,#945,#946,#947),.UNSPECIFIED.,.F.,.F.,(4,2,2,2,2,2,2,2,
2,2,4),(0.,0.0617740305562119,0.123031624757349,0.183965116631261,0.245045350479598,
0.316516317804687,0.388027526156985,0.469683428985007,0.551195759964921,0.603473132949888,
0.655802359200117),.UNSPECIFIED.);
#949=CARTESIAN_POINT('',(-19.676215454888,-9.19627166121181,1.7526));
#950=VERTEX_POINT('',#949);
#951=EDGE_CURVE('E386',#864,#950,#948,.T.);
#952=ORIENTED_EDGE('',*,*,#951,.T.);
#953=CARTESIAN_POINT('',(-19.3150833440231,-10.4234714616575,1.7526));
#954=CARTESIAN_POINT('',(-19.3267510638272,-10.5099207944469,1.7526));
#955=CARTESIAN_POINT('',(-19.3456700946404,-10.59545276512,1.7526));
#956=CARTESIAN_POINT('',(-19.3975725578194,-10.7622144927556,1.7526));
#957=CARTESIAN_POINT('',(-19.430571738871,-10.8434393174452,1.7526));
#958=CARTESIAN_POINT('',(-19.5097812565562,-10.9991847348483,1.7526));
#959=CARTESIAN_POINT('',(-19.5559916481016,-11.073705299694,1.7526));
#960=CARTESIAN_POINT('',(-19.6603625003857,-11.2138214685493,1.7526));
#961=CARTESIAN_POINT('',(-19.7185197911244,-11.2794194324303,1.7526));
#962=CARTESIAN_POINT('',(-19.844620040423,-11.3992249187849,1.7526));
#963=CARTESIAN_POINT('',(-19.9124742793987,-11.4535257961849,1.7526));
#964=CARTESIAN_POINT('',(-20.0564271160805,-11.5498085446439,1.7526));
#965=CARTESIAN_POINT('',(-20.1325255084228,-11.5917907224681,1.7526));
#966=CARTESIAN_POINT('',(-20.2898572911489,-11.6617441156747,1.7526));
#967=CARTESIAN_POINT('',(-20.3710213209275,-11.6898713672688,1.7526));
#968=CARTESIAN_POINT('',(-20.5369384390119,-11.7319821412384,1.7526));
#969=CARTESIAN_POINT('',(-20.6216913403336,-11.7459663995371,1.7526));
#970=CARTESIAN_POINT('',(-20.7916877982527,-11.7593150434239,1.7526));
#971=CARTESIAN_POINT('',(-20.8769226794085,-11.758790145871,1.7526));
#972=CARTESIAN_POINT('',(-21.0460879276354,-11.7434101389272,1.7526));
#973=CARTESIAN_POINT('',(-21.1300183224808,-11.7285553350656,1.7526));
#974=CARTESIAN_POINT('',(-21.2940485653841,-11.6850000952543,1.7526));
#975=CARTESIAN_POINT('',(-21.3741547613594,-11.65632354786,1.7526));
#976=CARTESIAN_POINT('',(-21.5284463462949,-11.5859875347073,1.7526));
#977=CARTESIAN_POINT('',(-21.6026316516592,-11.5443278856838,1.7526));
#978=CARTESIAN_POINT('',(-21.7433532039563,-11.4490310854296,1.7526));
#979=CARTESIAN_POINT('',(-21.8098531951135,-11.395340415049,1.7526));
#980=CARTESIAN_POINT('',(-21.9330015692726,-11.2776536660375,1.7526));
#981=CARTESIAN_POINT('',(-21.9896495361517,-11.2136571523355,1.7526));
#982=CARTESIAN_POINT('',(-22.0920815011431,-11.0765266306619,1.7526));
#983=CARTESIAN_POINT('',(-22.1377555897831,-11.0033105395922,1.7526));
#984=CARTESIAN_POINT('',(-22.2163323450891,-10.8503205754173,1.7526));
#985=CARTESIAN_POINT('',(-22.2492342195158,-10.7705462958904,1.7526));
#986=CARTESIAN_POINT('',(-22.3017495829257,-10.6056771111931,1.7526));
#987=CARTESIAN_POINT('',(-22.3211981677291,-10.5205296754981,1.7526));
#988=CARTESIAN_POINT('',(-22.345685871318,-10.3481871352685,1.7526));
#989=CARTESIAN_POINT('',(-22.3507240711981,-10.2609919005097,1.7526));
#990=CARTESIAN_POINT('',(-22.3462690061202,-10.0860676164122,1.7526));
#991=CARTESIAN_POINT('',(-22.3366247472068,-9.9983423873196,1.7526));
#992=CARTESIAN_POINT('',(-22.3028052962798,-9.82573625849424,1.7526));
#993=CARTESIAN_POINT('',(-22.2786295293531,-9.74085547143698,1.7526));
#994=CARTESIAN_POINT('',(-22.2162810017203,-9.57603272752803,1.7526));
#995=CARTESIAN_POINT('',(-22.1780563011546,-9.49611040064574,1.7526));
#996=CARTESIAN_POINT('',(-22.0886474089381,-9.34387181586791,1.7526));
#997=CARTESIAN_POINT('',(-22.0374634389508,-9.27155542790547,1.7526));
#998=CARTESIAN_POINT('',(-21.9239035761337,-9.13713540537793,1.7526));
#999=CARTESIAN_POINT('',(-21.8616038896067,-9.07496743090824,1.7526));
#1000=CARTESIAN_POINT('',(-21.7273028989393,-8.96217864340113,1.7526));
#1001=CARTESIAN_POINT('',(-21.655302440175,-8.91155682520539,1.7526));
#1002=CARTESIAN_POINT('',(-21.504866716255,-8.82418439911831,1.7526));
#1003=CARTESIAN_POINT('',(-21.4265529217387,-8.78722469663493,1.7526));
#1004=CARTESIAN_POINT('',(-21.2647570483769,-8.72724829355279,1.7526));
#1005=CARTESIAN_POINT('',(-21.1812755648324,-8.70422999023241,1.7526));
#1006=CARTESIAN_POINT('',(-21.0130961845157,-8.67317714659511,1.7526));
#1007=CARTESIAN_POINT('',(-20.9284456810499,-8.66488559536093,1.7526));
#1008=CARTESIAN_POINT('',(-20.75896639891,-8.66276581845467,1.7526));
#1009=CARTESIAN_POINT('',(-20.6741376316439,-8.66893669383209,1.7526));
#1010=CARTESIAN_POINT('',(-20.5074553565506,-8.69542461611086,1.7526));
#1011=CARTESIAN_POINT('',(-20.4255828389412,-8.71562237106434,1.7526));
#1012=CARTESIAN_POINT('',(-20.2663581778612,-8.7693930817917,1.7526));
#1013=CARTESIAN_POINT('',(-20.1890061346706,-8.80296633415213,1.7526));
#1014=CARTESIAN_POINT('',(-20.0404658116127,-8.88270184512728,1.7526));
#1015=CARTESIAN_POINT('',(-19.9693193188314,-8.92894188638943,1.7526));
#1016=CARTESIAN_POINT('',(-19.8356369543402,-9.03252513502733,1.7526));
#1017=CARTESIAN_POINT('',(-19.7731014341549,-9.08986879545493,1.7526));
#1018=CARTESIAN_POINT('',(-19.6573040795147,-9.21503446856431,1.7526));
#1019=CARTESIAN_POINT('',(-19.6042122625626,-9.28301374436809,1.7526));
#1020=CARTESIAN_POINT('',(-19.5099544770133,-9.42681595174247,1.7526));
#1021=CARTESIAN_POINT('',(-19.468792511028,-9.50264150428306,1.7526));
#1022=CARTESIAN_POINT('',(-19.3988597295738,-9.66138327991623,1.7526));
#1023=CARTESIAN_POINT('',(-19.3703173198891,-9.74440003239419,1.7526));
#1024=CARTESIAN_POINT('',(-19.3274692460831,-9.9139596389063,1.7526));
#1025=CARTESIAN_POINT('',(-19.3131477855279,-10.0004984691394,1.7526));
#1026=CARTESIAN_POINT('',(-19.3015911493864,-10.1435120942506,1.7526));
#1027=CARTESIAN_POINT('',(-19.3000782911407,-10.1996759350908,1.7526));
#1028=CARTESIAN_POINT('',(-19.3030706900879,-10.31184360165,1.7526));
#1029=CARTESIAN_POINT('',(-19.3075759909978,-10.3678474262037,1.7526));
#1030=CARTESIAN_POINT('',(-19.3150833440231,-10.4234714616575,1.7526));
#1031=B_SPLINE_CURVE_WITH_KNOTS('',3,(#953,#954,#955,#956,#957,#958,#959,#960,#961,#962,#963,
#964,#965,#966,#967,#968,#969,#970,#971,#972,#973,#974,#975,#976,#977,#978,#979,#980,#981,#982,
#983,#984,#985,#986,#987,#988,#989,#990,#991,#992,#993,#994,#995,#996,#997,#998,#999,#1000,
#1001,#1002,#1003,#1004,#1005,#1006,#1007,#1008,#1009,#1010,#1011,#1012,#1013,#1014,#1015,#1016,
#1017,#1018,#1019,#1020,#1021,#1022,#1023,#1024,#1025,#1026,#1027,#1028,#1029,#1030),
.UNSPECIFIED.,.T.,.F.,(4,2,2,2,2,2,2,2,2,2,2,2,2,2,2,2,2,2,2,2,2,2,2,2,2,2,2,2,2,2,2,2,2,2,2,2,
2,2,4),(0.,0.26149736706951,0.523287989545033,0.785079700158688,1.0468020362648,
1.30626721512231,1.56572593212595,1.82219167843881,2.07864407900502,2.33314007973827,
2.58763065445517,2.84168295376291,3.09573883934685,3.35094813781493,3.60616821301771,
3.86384682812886,4.12154142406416,4.38234127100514,4.64315774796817,4.90667463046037,
5.17020193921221,5.43471349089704,5.69922051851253,5.96197934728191,6.22471529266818,
6.48324500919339,6.74174499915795,6.99568760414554,7.24961442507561,7.50140774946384,
7.75320665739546,8.00658785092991,8.25997938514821,8.5175513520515,8.77520963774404,
9.03735746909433,9.29921378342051,9.46746763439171,9.63572270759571),.UNSPECIFIED.);
#1032=EDGE_CURVE('E303',#950,#392,#1031,.T.);
#1033=ORIENTED_EDGE('',*,*,#1032,.T.);
#1034=ORIENTED_EDGE('',*,*,#393,.F.);
#1035=ORIENTED_EDGE('',*,*,#97,.T.);
#1036=CARTESIAN_POINT('',(-19.4884357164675,-10.0981174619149,4.5974));
#1037=CARTESIAN_POINT('',(-19.4431238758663,-10.0072256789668,4.5974));
#1038=CARTESIAN_POINT('',(-19.4058597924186,-9.91218822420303,4.5974));
#1039=CARTESIAN_POINT('',(-19.3478920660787,-9.71705855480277,4.5974));
#1040=CARTESIAN_POINT('',(-19.3272289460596,-9.61695460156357,4.5974));
#1041=CARTESIAN_POINT('',(-19.3025537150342,-9.41507207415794,4.5974));
#1042=CARTESIAN_POINT('',(-19.2984848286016,-9.31330040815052,4.5974));
#1043=CARTESIAN_POINT('',(-19.3065678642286,-9.11046521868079,4.5974));
#1044=CARTESIAN_POINT('',(-19.3187136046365,-9.00940144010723,4.5974));
#1045=CARTESIAN_POINT('',(-19.3598689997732,-8.80522160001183,4.5974));
#1046=CARTESIAN_POINT('',(-19.3897293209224,-8.70227568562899,4.5974));
#1047=CARTESIAN_POINT('',(-19.4664359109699,-8.50283987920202,4.5974));
#1048=CARTESIAN_POINT('',(-19.5132892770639,-8.40635270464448,4.5974));
#1049=CARTESIAN_POINT('',(-19.6228176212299,-8.22390779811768,4.5974));
#1050=CARTESIAN_POINT('',(-19.6853499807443,-8.13786500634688,4.5974));
#1051=CARTESIAN_POINT('',(-19.8254494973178,-7.97896409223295,4.5974));
#1052=CARTESIAN_POINT('',(-19.9030068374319,-7.90609742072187,4.5974));
#1053=CARTESIAN_POINT('',(-20.0628831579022,-7.7841267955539,4.5974));
#1054=CARTESIAN_POINT('',(-20.1439328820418,-7.73336737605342,4.5974));
#1055=CARTESIAN_POINT('',(-20.3145009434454,-7.64899558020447,4.5974));
#1056=CARTESIAN_POINT('',(-20.4040060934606,-7.61535700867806,4.5974));
#1057=CARTESIAN_POINT('',(-20.5743699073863,-7.57131543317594,4.5974));
#1058=CARTESIAN_POINT('',(-20.6545314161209,-7.55819832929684,4.5974));
#1059=CARTESIAN_POINT('',(-20.8158853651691,-7.54705871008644,4.5974));
#1060=CARTESIAN_POINT('',(-20.8970771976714,-7.54902767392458,4.5974));
#1061=CARTESIAN_POINT('',(-21.0505608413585,-7.56706759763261,4.5974));
#1062=CARTESIAN_POINT('',(-21.1230055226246,-7.58187811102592,4.5974));
#1063=CARTESIAN_POINT('',(-21.2644939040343,-7.62310840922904,4.5974));
#1064=CARTESIAN_POINT('',(-21.3335373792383,-7.64952896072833,4.5974));
#1065=CARTESIAN_POINT('',(-21.4686612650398,-7.71369502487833,4.5974));
#1066=CARTESIAN_POINT('',(-21.5345907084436,-7.75175642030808,4.5974));
#1067=CARTESIAN_POINT('',(-21.6599847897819,-7.83732247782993,4.5974));
#1068=CARTESIAN_POINT('',(-21.7194469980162,-7.88483067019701,4.5974));
#1069=CARTESIAN_POINT('',(-21.8374649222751,-7.99360900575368,4.5974));
#1070=CARTESIAN_POINT('',(-21.8951417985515,-8.05583114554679,4.5974));
#1071=CARTESIAN_POINT('',(-22.0007342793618,-8.18805769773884,4.5974));
#1072=CARTESIAN_POINT('',(-22.0486448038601,-8.25806613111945,4.5974));
#1073=CARTESIAN_POINT('',(-22.1400214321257,-8.41397202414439,4.5974));
#1074=CARTESIAN_POINT('',(-22.1820089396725,-8.50073765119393,4.5974));
#1075=CARTESIAN_POINT('',(-22.2522832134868,-8.67965562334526,4.5974));
#1076=CARTESIAN_POINT('',(-22.2805632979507,-8.77181057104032,4.5974));
#1077=CARTESIAN_POINT('',(-22.325023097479,-8.96827578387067,4.5974));
#1078=CARTESIAN_POINT('',(-22.3397938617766,-9.07290781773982,4.5974));
#1079=CARTESIAN_POINT('',(-22.3519212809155,-9.28320272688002,4.5974));
#1080=CARTESIAN_POINT('',(-22.3492737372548,-9.38886584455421,4.5974));
#1081=CARTESIAN_POINT('',(-22.3260216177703,-9.60012502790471,4.5974));
#1082=CARTESIAN_POINT('',(-22.3051012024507,-9.70568705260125,4.5974));
#1083=CARTESIAN_POINT('',(-22.2447914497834,-9.91143107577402,4.5974));
#1084=CARTESIAN_POINT('',(-22.2054066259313,-10.0116143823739,4.5974));
#1085=CARTESIAN_POINT('',(-22.1113041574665,-10.1975688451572,4.5974));
#1086=CARTESIAN_POINT('',(-22.0575618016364,-10.2838317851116,4.5974));
#1087=CARTESIAN_POINT('',(-21.9349820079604,-10.4448917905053,4.5974));
#1088=CARTESIAN_POINT('',(-21.8661541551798,-10.5196960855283,4.5974));
#1089=CARTESIAN_POINT('',(-21.7222005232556,-10.648247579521,4.5974));
#1090=CARTESIAN_POINT('',(-21.6482409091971,-10.703300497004,4.5974));
#1091=CARTESIAN_POINT('',(-21.491433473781,-10.7988229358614,4.5974));
#1092=CARTESIAN_POINT('',(-21.408591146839,-10.8393014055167,4.5974));
#1093=CARTESIAN_POINT('',(-21.2440977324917,-10.9010085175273,4.5974));
#1094=CARTESIAN_POINT('',(-21.1629521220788,-10.9235887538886,4.5974));
#1095=CARTESIAN_POINT('',(-20.9979482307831,-10.9540121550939,4.5974));
#1096=CARTESIAN_POINT('',(-20.914090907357,-10.9618604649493,4.5974));
#1097=CARTESIAN_POINT('',(-20.750489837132,-10.9624691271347,4.5974));
#1098=CARTESIAN_POINT('',(-20.6707477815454,-10.9559565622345,4.5974));
#1099=CARTESIAN_POINT('',(-20.5135168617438,-10.9295843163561,4.5974));
#1100=CARTESIAN_POINT('',(-20.4360276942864,-10.909726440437,4.5974));
#1101=CARTESIAN_POINT('',(-20.2856594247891,-10.8575171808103,4.5974));
#1102=CARTESIAN_POINT('',(-20.2127671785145,-10.8252034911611,4.5974));
#1103=CARTESIAN_POINT('',(-20.073132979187,-10.7492417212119,4.5974));
#1104=CARTESIAN_POINT('',(-20.0063937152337,-10.7055887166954,4.5974));
#1105=CARTESIAN_POINT('',(-19.8779871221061,-10.6064257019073,4.5974));
#1106=CARTESIAN_POINT('',(-19.8166392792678,-10.5505034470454,4.5974));
#1107=CARTESIAN_POINT('',(-19.7034988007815,-10.4298220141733,4.5974));
#1108=CARTESIAN_POINT('',(-19.6516957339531,-10.3650726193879,4.5974));
#1109=CARTESIAN_POINT('',(-19.5833662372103,-10.2651346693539,4.5974));
#1110=CARTESIAN_POINT('',(-19.5627846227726,-10.2326451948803,4.5974));
#1111=CARTESIAN_POINT('',(-19.5238963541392,-10.1663408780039,4.5974));
#1112=CARTESIAN_POINT('',(-19.5055893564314,-10.1325262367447,4.5974));
#1113=CARTESIAN_POINT('',(-19.4884357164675,-10.0981174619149,4.5974));
#1114=B_SPLINE_CURVE_WITH_KNOTS('',3,(#1036,#1037,#1038,#1039,#1040,#1041,#1042,#1043,#1044,
#1045,#1046,#1047,#1048,#1049,#1050,#1051,#1052,#1053,#1054,#1055,#1056,#1057,#1058,#1059,#1060,
#1061,#1062,#1063,#1064,#1065,#1066,#1067,#1068,#1069,#1070,#1071,#1072,#1073,#1074,#1075,#1076,
#1077,#1078,#1079,#1080,#1081,#1082,#1083,#1084,#1085,#1086,#1087,#1088,#1089,#1090,#1091,#1092,
#1093,#1094,#1095,#1096,#1097,#1098,#1099,#1100,#1101,#1102,#1103,#1104,#1105,#1106,#1107,#1108,
#1109,#1110,#1111,#1112,#1113),.UNSPECIFIED.,.T.,.F.,(4,2,2,2,2,2,2,2,2,2,2,2,2,2,2,2,2,2,2,2,2,
2,2,2,2,2,2,2,2,2,2,2,2,2,2,2,2,2,4),(0.,0.304531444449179,0.609804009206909,0.914031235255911,
1.21814251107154,1.5381959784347,1.85838327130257,2.17575753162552,2.49292512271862,
2.7781027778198,3.0628427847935,3.30518216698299,3.54738468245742,3.76820258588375,
3.98903507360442,4.21649055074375,4.4440311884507,4.69755435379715,4.95120905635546,
5.23918632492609,5.52730382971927,5.84286152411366,6.15849528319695,6.47969507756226,
6.80081639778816,7.10406657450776,7.40712462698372,7.68223431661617,7.95717480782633,
8.20857126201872,8.45987990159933,8.69875826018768,8.93760431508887,9.17573317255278,
9.41396561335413,9.66195085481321,9.90966345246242,10.0249669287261,10.1402529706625),.UNSPECIFIED.);
#1115=EDGE_CURVE('E428',#87,#29,#1114,.T.);
#1116=ORIENTED_EDGE('',*,*,#1115,.T.);
#1117=ORIENTED_EDGE('',*,*,#39,.F.);
#1118=ORIENTED_EDGE('',*,*,#802,.T.);
#1119=ORIENTED_EDGE('',*,*,#122,.T.);
#1120=ORIENTED_EDGE('',*,*,#338,.F.);
#1121=EDGE_LOOP('',(#899,#924,#925,#952,#1033,#1034,#1035,#1116,#1117,#1118,#1119,#1120));
#1122=FACE_BOUND('',#1121,.T.);
#1123=ADVANCED_FACE('F315',(#1122),#898,.F.);
#1124=DIRECTION('',(1.,0.,0.));
#1125=VECTOR('',#1124,1.);
#1126=CARTESIAN_POINT('',(-47.752,-21.0540472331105,1.7526));
#1127=LINE('',#1126,#1125);
#1128=CARTESIAN_POINT('',(-7.40409999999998,-21.0540472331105,1.7526));
#1129=VERTEX_POINT('',#1128);
#1130=EDGE_CURVE('E478',#1129,#518,#1127,.F.);
#1131=ORIENTED_EDGE('',*,*,#1130,.F.);
#1132=CARTESIAN_POINT('',(-7.40409999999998,-15.748,0.));
#1133=DIRECTION('',(1.,0.,0.));
#1134=DIRECTION('',(0.,0.,-1.));
#1135=AXIS2_PLACEMENT_3D('',#1132,#1133,#1134);
#1136=CIRCLE('',#1135,5.588);
#1137=CARTESIAN_POINT('',(-7.40409999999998,-18.9244220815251,4.5974));
#1138=VERTEX_POINT('',#1137);
#1139=EDGE_CURVE('E416',#1129,#1138,#1136,.F.);
#1140=ORIENTED_EDGE('',*,*,#1139,.T.);
#1141=DIRECTION('',(1.,0.,0.));
#1142=VECTOR('',#1141,1.);
#1143=CARTESIAN_POINT('',(-47.752,-18.9244220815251,4.5974));
#1144=LINE('',#1143,#1142);
#1145=EDGE_CURVE('E269',#499,#1138,#1144,.T.);
#1146=ORIENTED_EDGE('',*,*,#1145,.F.);
#1147=ORIENTED_EDGE('',*,*,#500,.F.);
#1148=ORIENTED_EDGE('',*,*,#521,.F.);
#1149=EDGE_LOOP('',(#1131,#1140,#1146,#1147,#1148));
#1150=FACE_BOUND('',#1149,.T.);
#1151=ADVANCED_FACE('F241',(#1150),#530,.T.);
#1152=CARTESIAN_POINT('',(-47.752,-7.54952779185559,4.5974));
#1153=DIRECTION('',(0.,0.,1.));
#1154=DIRECTION('',(0.,-1.,0.));
#1155=AXIS2_PLACEMENT_3D('',#1152,#1153,#1154);
#1156=PLANE('',#1155);
#1157=ORIENTED_EDGE('',*,*,#1145,.T.);
#1158=CARTESIAN_POINT('',(-7.40409999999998,-18.9244220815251,4.5974));
#1159=CARTESIAN_POINT('',(-7.35486767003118,-18.8378020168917,4.5974));
#1160=CARTESIAN_POINT('',(-7.30665568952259,-18.750600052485,4.5974));
#1161=CARTESIAN_POINT('',(-7.21258023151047,-18.5749114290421,4.5974));
#1162=CARTESIAN_POINT('',(-7.16671735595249,-18.4864244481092,4.5974));
#1163=CARTESIAN_POINT('',(-7.03370537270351,-18.2200308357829,4.5974));
#1164=CARTESIAN_POINT('',(-6.95051233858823,-18.0401157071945,4.5974));
#1165=CARTESIAN_POINT('',(-6.79787264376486,-17.6740416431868,4.5974));
#1166=CARTESIAN_POINT('',(-6.72845003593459,-17.4878724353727,4.5974));
#1167=CARTESIAN_POINT('',(-6.60724781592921,-17.1086960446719,4.5974));
#1168=CARTESIAN_POINT('',(-6.55557764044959,-16.9156542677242,4.5974));
#1169=CARTESIAN_POINT('',(-6.51509999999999,-16.7198612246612,4.5974));
#1170=B_SPLINE_CURVE_WITH_KNOTS('',3,(#1158,#1159,#1160,#1161,#1162,#1163,#1164,#1165,#1166,
#1167,#1168,#1169),.UNSPECIFIED.,.F.,.F.,(4,2,2,2,2,4),(0.,0.298892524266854,0.597861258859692,
1.19207834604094,1.78732438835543,2.38617667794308),.UNSPECIFIED.);
#1171=CARTESIAN_POINT('',(-6.51509999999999,-16.7198612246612,4.5974));
#1172=VERTEX_POINT('',#1171);
#1173=EDGE_CURVE('E334',#1138,#1172,#1170,.T.);
#1174=ORIENTED_EDGE('',*,*,#1173,.T.);
#1175=DIRECTION('',(0.,1.,0.));
#1176=VECTOR('',#1175,1.);
#1177=CARTESIAN_POINT('',(-6.5151,-7.54952779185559,4.5974));
#1178=LINE('',#1177,#1176);
#1179=EDGE_CURVE('E266',#1172,#54,#1178,.T.);
#1180=ORIENTED_EDGE('',*,*,#1179,.T.);
#1181=ORIENTED_EDGE('',*,*,#55,.F.);
#1182=ORIENTED_EDGE('',*,*,#1115,.F.);
#1183=ORIENTED_EDGE('',*,*,#88,.F.);
#1184=ORIENTED_EDGE('',*,*,#411,.F.);
#1185=ORIENTED_EDGE('',*,*,#436,.F.);
#1186=ORIENTED_EDGE('',*,*,#458,.F.);
#1187=ORIENTED_EDGE('',*,*,#507,.F.);
#1188=EDGE_LOOP('',(#1157,#1174,#1180,#1181,#1182,#1183,#1184,#1185,#1186,#1187));
#1189=FACE_BOUND('',#1188,.T.);
#1190=ORIENTED_EDGE('',*,*,#369,.F.);
#1191=EDGE_LOOP('',(#1190));
#1192=FACE_BOUND('',#1191,.T.);
#1193=ADVANCED_FACE('F322',(#1189,#1192),#1156,.T.);
#1194=CARTESIAN_POINT('',(-15.8260487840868,-19.2269271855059,1.7526));
#1195=DIRECTION('',(0.,0.,1.));
#1196=DIRECTION('',(1.,0.,0.));
#1197=AXIS2_PLACEMENT_3D('',#1194,#1195,#1196);
#1198=PLANE('',#1197);
#1199=DIRECTION('',(0.,-1.,0.));
#1200=VECTOR('',#1199,1.);
#1201=CARTESIAN_POINT('',(-6.51509999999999,-6.2484,1.7526));
#1202=LINE('',#1201,#1200);
#1203=CARTESIAN_POINT('',(-6.51509999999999,-13.8655778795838,1.7526));
#1204=VERTEX_POINT('',#1203);
#1205=CARTESIAN_POINT('',(-6.51509999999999,-20.1079305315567,1.7526));
#1206=VERTEX_POINT('',#1205);
#1207=EDGE_CURVE('E480',#1204,#1206,#1202,.T.);
#1208=ORIENTED_EDGE('',*,*,#1207,.T.);
#1209=CARTESIAN_POINT('',(-6.51509999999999,-20.1079305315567,1.7526));
#1210=CARTESIAN_POINT('',(-6.58868744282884,-20.1872383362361,1.7526));
#1211=CARTESIAN_POINT('',(-6.66242233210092,-20.2664090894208,1.7526));
#1212=CARTESIAN_POINT('',(-6.81015021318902,-20.4245082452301,1.7526));
#1213=CARTESIAN_POINT('',(-6.88414320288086,-20.5034366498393,1.7526));
#1214=CARTESIAN_POINT('',(-7.03235155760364,-20.661084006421,1.7526));
#1215=CARTESIAN_POINT('',(-7.10656692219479,-20.7398029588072,1.7526));
#1216=CARTESIAN_POINT('',(-7.25519352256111,-20.8970569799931,1.7526));
#1217=CARTESIAN_POINT('',(-7.32960475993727,-20.9755920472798,1.7526));
#1218=CARTESIAN_POINT('',(-7.40409999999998,-21.0540472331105,1.7526));
#1219=B_SPLINE_CURVE_WITH_KNOTS('',3,(#1209,#1210,#1211,#1212,#1213,#1214,#1215,#1216,#1217,
#1218),.UNSPECIFIED.,.F.,.F.,(4,2,2,2,4),(0.,0.324566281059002,0.649129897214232,
0.973692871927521,1.29825850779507),.UNSPECIFIED.);
#1220=EDGE_CURVE('E277',#1206,#1129,#1219,.T.);
#1221=ORIENTED_EDGE('',*,*,#1220,.T.);
#1222=ORIENTED_EDGE('',*,*,#1130,.T.);
#1223=ORIENTED_EDGE('',*,*,#519,.F.);
#1224=ORIENTED_EDGE('',*,*,#471,.F.);
#1225=ORIENTED_EDGE('',*,*,#448,.F.);
#1226=ORIENTED_EDGE('',*,*,#425,.F.);
#1227=ORIENTED_EDGE('',*,*,#401,.F.);
#1228=ORIENTED_EDGE('',*,*,#1032,.F.);
#1229=CARTESIAN_POINT('',(-15.8260487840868,-19.2269271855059,1.7526));
#1230=DIRECTION('',(0.,0.,1.));
#1231=DIRECTION('',(1.,0.,0.));
#1232=AXIS2_PLACEMENT_3D('',#1229,#1230,#1231);
#1233=CIRCLE('',#1232,10.7442);
#1234=EDGE_CURVE('E578',#950,#1204,#1233,.F.);
#1235=ORIENTED_EDGE('',*,*,#1234,.T.);
#1236=EDGE_LOOP('',(#1208,#1221,#1222,#1223,#1224,#1225,#1226,#1227,#1228,#1235));
#1237=FACE_BOUND('',#1236,.T.);
#1238=ORIENTED_EDGE('',*,*,#358,.F.);
#1239=EDGE_LOOP('',(#1238));
#1240=FACE_BOUND('',#1239,.T.);
#1241=ADVANCED_FACE('F193',(#1237,#1240),#1198,.F.);
#1242=CARTESIAN_POINT('',(-7.40409999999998,-15.748,0.));
#1243=DIRECTION('',(-1.,0.,0.));
#1244=DIRECTION('',(0.,0.,1.));
#1245=AXIS2_PLACEMENT_3D('',#1242,#1243,#1244);
#1246=CONICAL_SURFACE('',#1245,5.588,0.785398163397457);
#1247=ORIENTED_EDGE('',*,*,#1220,.F.);
#1248=CARTESIAN_POINT('',(-6.51509999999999,-15.748,0.));
#1249=DIRECTION('',(1.,0.,0.));
#1250=DIRECTION('',(0.,0.,-1.));
#1251=AXIS2_PLACEMENT_3D('',#1248,#1249,#1250);
#1252=CIRCLE('',#1251,4.699);
#1253=EDGE_CURVE('E408',#1172,#1206,#1252,.T.);
#1254=ORIENTED_EDGE('',*,*,#1253,.F.);
#1255=ORIENTED_EDGE('',*,*,#1173,.F.);
#1256=ORIENTED_EDGE('',*,*,#1139,.F.);
#1257=EDGE_LOOP('',(#1247,#1254,#1255,#1256));
#1258=FACE_BOUND('',#1257,.T.);
#1259=ADVANCED_FACE('F321',(#1258),#1246,.T.);
#1260=CARTESIAN_POINT('',(-15.8260487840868,-19.2269271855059,1.3716));
#1261=DIRECTION('',(0.,0.,1.));
#1262=DIRECTION('',(1.,0.,0.));
#1263=AXIS2_PLACEMENT_3D('',#1260,#1261,#1262);
#1264=TOROIDAL_SURFACE('',#1263,10.7442,0.381);
#1265=CARTESIAN_POINT('',(-6.51509999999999,-13.8655778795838,1.7526));
#1266=CARTESIAN_POINT('',(-6.51509999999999,-13.8335517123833,1.75258690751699));
#1267=CARTESIAN_POINT('',(-6.51509999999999,-13.8015129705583,1.75159326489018));
#1268=CARTESIAN_POINT('',(-6.51509999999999,-13.7374805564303,1.7474676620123));
#1269=CARTESIAN_POINT('',(-6.51509999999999,-13.7054872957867,1.74432940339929));
#1270=CARTESIAN_POINT('',(-6.51509999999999,-13.641629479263,1.73571143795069));
#1271=CARTESIAN_POINT('',(-6.51509999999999,-13.609766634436,1.73021877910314));
#1272=CARTESIAN_POINT('',(-6.51509999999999,-13.5466377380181,1.71660746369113));
#1273=CARTESIAN_POINT('',(-6.51509999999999,-13.5153709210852,1.70849245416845));
#1274=CARTESIAN_POINT('',(-6.51509999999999,-13.4608123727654,1.69141729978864));
#1275=CARTESIAN_POINT('',(-6.51509999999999,-13.4373290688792,1.68307268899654));
#1276=CARTESIAN_POINT('',(-6.51509999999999,-13.3911985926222,1.66429770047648));
#1277=CARTESIAN_POINT('',(-6.51509999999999,-13.3685513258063,1.65386755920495));
#1278=CARTESIAN_POINT('',(-6.51509999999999,-13.3243552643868,1.63048161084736));
#1279=CARTESIAN_POINT('',(-6.51509999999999,-13.3028163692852,1.61750681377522));
#1280=CARTESIAN_POINT('',(-6.51509999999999,-13.2617779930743,1.58863043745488));
#1281=CARTESIAN_POINT('',(-6.51509999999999,-13.2422745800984,1.5727346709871));
#1282=CARTESIAN_POINT('',(-6.51509999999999,-13.2134515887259,1.5443229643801));
#1283=CARTESIAN_POINT('',(-6.51509999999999,-13.2031002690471,1.53285853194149));
#1284=CARTESIAN_POINT('',(-6.51509999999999,-13.1841094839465,1.50857384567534));
#1285=CARTESIAN_POINT('',(-6.51509999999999,-13.1754686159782,1.49575471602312));
#1286=CARTESIAN_POINT('',(-6.51509999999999,-13.1615866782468,1.47081790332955));
#1287=CARTESIAN_POINT('',(-6.51509999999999,-13.1560319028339,1.45887648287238));
#1288=CARTESIAN_POINT('',(-6.51509999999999,-13.1469918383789,1.43424257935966));
#1289=CARTESIAN_POINT('',(-6.51509999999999,-13.1435014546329,1.42155203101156));
#1290=CARTESIAN_POINT('',(-6.51509999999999,-13.1401047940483,1.40254928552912));
#1291=CARTESIAN_POINT('',(-6.51509999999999,-13.1392789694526,1.39639221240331));
#1292=CARTESIAN_POINT('',(-6.51509999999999,-13.1381735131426,1.38402469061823));
#1293=CARTESIAN_POINT('',(-6.51509999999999,-13.1378942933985,1.37781420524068));
#1294=CARTESIAN_POINT('',(-6.51509999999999,-13.1378954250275,1.37160000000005));
#1295=B_SPLINE_CURVE_WITH_KNOTS('',3,(#1265,#1266,#1267,#1268,#1269,#1270,#1271,#1272,#1273,
#1274,#1275,#1276,#1277,#1278,#1279,#1280,#1281,#1282,#1283,#1284,#1285,#1286,#1287,#1288,#1289,
#1290,#1291,#1292,#1293,#1294),.UNSPECIFIED.,.F.,.F.,(4,2,2,2,2,2,2,2,2,2,2,2,2,2,4),(0.,
0.0960829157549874,0.192449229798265,0.289352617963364,0.386121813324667,0.460806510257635,
0.535482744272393,0.610739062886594,0.685847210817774,0.732067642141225,0.778250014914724,
0.817608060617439,0.85686856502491,0.875483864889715,0.894113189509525),.UNSPECIFIED.);
#1296=EDGE_CURVE('E395',#1204,#881,#1295,.T.);
#1297=ORIENTED_EDGE('',*,*,#1296,.F.);
#1298=ORIENTED_EDGE('',*,*,#1234,.F.);
#1299=ORIENTED_EDGE('',*,*,#951,.F.);
#1300=ORIENTED_EDGE('',*,*,#889,.F.);
#1301=EDGE_LOOP('',(#1297,#1298,#1299,#1300));
#1302=FACE_BOUND('',#1301,.T.);
#1303=ADVANCED_FACE('F343',(#1302),#1264,.F.);
#1304=CARTESIAN_POINT('',(-15.8260487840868,-19.2269271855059,-1.3716));
#1305=DIRECTION('',(0.,0.,1.));
#1306=DIRECTION('',(1.,0.,0.));
#1307=AXIS2_PLACEMENT_3D('',#1304,#1305,#1306);
#1308=TOROIDAL_SURFACE('',#1307,10.7442,0.381);
#1309=CARTESIAN_POINT('',(-6.51509999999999,-13.1378954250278,-1.3716));
#1310=CARTESIAN_POINT('',(-6.51509999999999,-13.137865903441,-1.3840762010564));
#1311=CARTESIAN_POINT('',(-6.51509999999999,-13.1390133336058,-1.39652025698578));
#1312=CARTESIAN_POINT('',(-6.51509999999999,-13.143403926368,-1.42092964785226));
#1313=CARTESIAN_POINT('',(-6.51509999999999,-13.1466293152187,-1.43289813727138));
#1314=CARTESIAN_POINT('',(-6.51509999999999,-13.1549129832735,-1.45612835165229));
#1315=CARTESIAN_POINT('',(-6.51509999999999,-13.1599657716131,-1.46739207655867));
#1316=CARTESIAN_POINT('',(-6.51509999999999,-13.1715829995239,-1.48912801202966));
#1317=CARTESIAN_POINT('',(-6.51509999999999,-13.1781508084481,-1.49959838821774));
#1318=CARTESIAN_POINT('',(-6.51509999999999,-13.1973254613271,-1.52645149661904));
#1319=CARTESIAN_POINT('',(-6.51509999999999,-13.2110176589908,-1.5420587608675));
#1320=CARTESIAN_POINT('',(-6.51509999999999,-13.240635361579,-1.57096997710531));
#1321=CARTESIAN_POINT('',(-6.51509999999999,-13.2565663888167,-1.58426804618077));
#1322=CARTESIAN_POINT('',(-6.51509999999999,-13.301301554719,-1.61721965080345));
#1323=CARTESIAN_POINT('',(-6.51509999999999,-13.3314670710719,-1.63501148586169));
#1324=CARTESIAN_POINT('',(-6.51509999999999,-13.3941426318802,-1.66609189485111));
#1325=CARTESIAN_POINT('',(-6.51509999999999,-13.4266658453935,-1.67935236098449));
#1326=CARTESIAN_POINT('',(-6.51509999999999,-13.4927560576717,-1.70204373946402));
#1327=CARTESIAN_POINT('',(-6.51509999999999,-13.5263146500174,-1.71149959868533));
#1328=CARTESIAN_POINT('',(-6.51509999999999,-13.5942010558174,-1.72728671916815));
#1329=CARTESIAN_POINT('',(-6.51509999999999,-13.6285300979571,-1.73361255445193));
#1330=CARTESIAN_POINT('',(-6.51509999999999,-13.696638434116,-1.74337106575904));
#1331=CARTESIAN_POINT('',(-6.51509999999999,-13.7304074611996,-1.74687741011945));
#1332=CARTESIAN_POINT('',(-6.51509999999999,-13.7979824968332,-1.75147914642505));
#1333=CARTESIAN_POINT('',(-6.51509999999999,-13.8317878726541,-1.75258368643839));
#1334=CARTESIAN_POINT('',(-6.51509999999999,-13.8655778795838,-1.7526));
#1335=B_SPLINE_CURVE_WITH_KNOTS('',3,(#1309,#1310,#1311,#1312,#1313,#1314,#1315,#1316,#1317,
#1318,#1319,#1320,#1321,#1322,#1323,#1324,#1325,#1326,#1327,#1328,#1329,#1330,#1331,#1332,#1333,
#1334),.UNSPECIFIED.,.F.,.F.,(4,2,2,2,2,2,2,2,2,2,2,2,4),(0.,0.0373248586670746,
0.074334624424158,0.111234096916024,0.14821643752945,0.210142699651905,0.272224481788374,
0.376703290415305,0.481818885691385,0.586233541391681,0.690828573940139,0.792592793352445,
0.893968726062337),.UNSPECIFIED.);
#1336=EDGE_CURVE('E381',#873,#585,#1335,.T.);
#1337=ORIENTED_EDGE('',*,*,#1336,.F.);
#1338=ORIENTED_EDGE('',*,*,#874,.F.);
#1339=ORIENTED_EDGE('',*,*,#923,.F.);
#1340=ORIENTED_EDGE('',*,*,#595,.F.);
#1341=EDGE_LOOP('',(#1337,#1338,#1339,#1340));
#1342=FACE_BOUND('',#1341,.T.);
#1343=ADVANCED_FACE('F353',(#1342),#1308,.F.);
#1344=CARTESIAN_POINT('',(-6.51509999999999,-6.2484,0.));
#1345=DIRECTION('',(1.,0.,0.));
#1346=DIRECTION('',(0.,0.,-1.));
#1347=AXIS2_PLACEMENT_3D('',#1344,#1345,#1346);
#1348=PLANE('',#1347);
#1349=ORIENTED_EDGE('',*,*,#586,.T.);
#1350=ORIENTED_EDGE('',*,*,#822,.T.);
#1351=ORIENTED_EDGE('',*,*,#700,.F.);
#1352=ORIENTED_EDGE('',*,*,#63,.F.);
#1353=ORIENTED_EDGE('',*,*,#1179,.F.);
#1354=ORIENTED_EDGE('',*,*,#1253,.T.);
#1355=ORIENTED_EDGE('',*,*,#1207,.F.);
#1356=ORIENTED_EDGE('',*,*,#1296,.T.);
#1357=ORIENTED_EDGE('',*,*,#882,.F.);
#1358=ORIENTED_EDGE('',*,*,#1336,.T.);
#1359=EDGE_LOOP('',(#1349,#1350,#1351,#1352,#1353,#1354,#1355,#1356,#1357,#1358));
#1360=FACE_BOUND('',#1359,.T.);
#1361=ADVANCED_FACE('F360',(#1360),#1348,.T.);
#1362=CLOSED_SHELL('',(#43,#74,#107,#126,#154,#187,#243,#274,#307,#350,#373,#416,#440,#462,#511,
#525,#558,#688,#810,#828,#893,#1123,#1151,#1193,#1241,#1259,#1303,#1343,#1361));
#1363=MANIFOLD_SOLID_BREP('B2',#1362);
#1364=ADVANCED_BREP_SHAPE_REPRESENTATION('',(#18,#1363),#14);
#1365=SHAPE_DEFINITION_REPRESENTATION(#9,#1364);
ENDSEC;
END-ISO-10303-21;
